VERSION 5.8 ;
BUSBITCHARS "[]" ;
DIVIDERCHAR "/" ;
UNITS
    DATABASE MICRONS 1000 ;
END UNITS

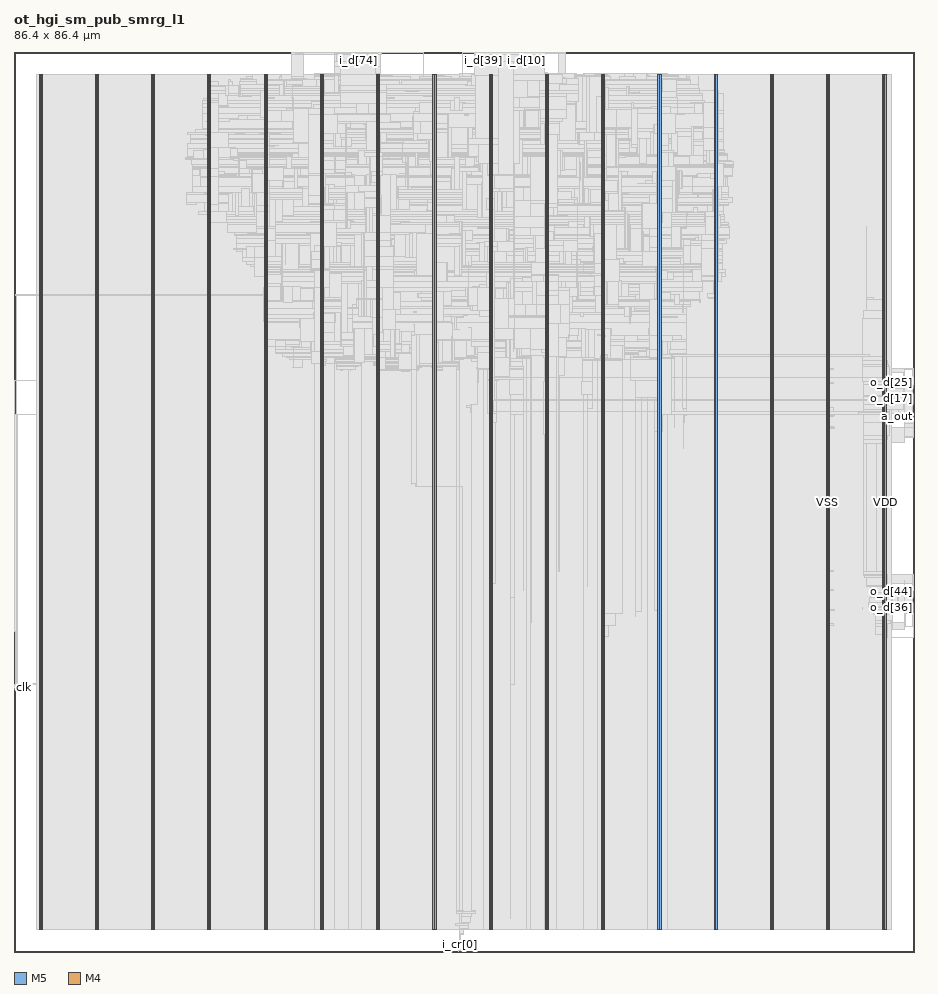
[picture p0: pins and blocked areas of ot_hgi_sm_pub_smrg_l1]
MACRO ot_hgi_sm_pub_smrg_l1
  FOREIGN ot_hgi_sm_pub_smrg_l1 0 0 ;
  CLASS BLOCK ;
  SIZE 86.4 BY 86.4 ;
  PIN a_in[0]
    DIRECTION INPUT ;
    USE SIGNAL ;
    PORT
      LAYER M5 ;
        RECT  48.048 86.316 48.072 86.4 ;
    END
  END a_in[0]
  PIN a_in[1]
    DIRECTION INPUT ;
    USE SIGNAL ;
    PORT
      LAYER M5 ;
        RECT  48.144 86.316 48.168 86.4 ;
    END
  END a_in[1]
  PIN a_out
    DIRECTION OUTPUT ;
    USE SIGNAL ;
    PORT
      LAYER M4 ;
        RECT  86.316 51.408 86.4 51.432 ;
    END
  END a_out
  PIN clk
    DIRECTION INPUT ;
    USE SIGNAL ;
    PORT
      LAYER M4 ;
        RECT  0 25.392 0.084 25.416 ;
    END
  END clk
  PIN i_cr[0]
    DIRECTION OUTPUT ;
    USE SIGNAL ;
    PORT
      LAYER M5 ;
        RECT  42.768 0 42.792 0.084 ;
    END
  END i_cr[0]
  PIN i_cr[1]
    DIRECTION OUTPUT ;
    USE SIGNAL ;
    PORT
      LAYER M5 ;
        RECT  42.864 0 42.888 0.084 ;
    END
  END i_cr[1]
  PIN i_d[0]
    DIRECTION INPUT ;
    USE SIGNAL ;
    PORT
      LAYER M5 ;
        RECT  48.24 86.316 48.264 86.4 ;
    END
  END i_d[0]
  PIN i_d[100]
    DIRECTION INPUT ;
    USE SIGNAL ;
    PORT
      LAYER M5 ;
        RECT  31.344 86.316 31.368 86.4 ;
    END
  END i_d[100]
  PIN i_d[101]
    DIRECTION INPUT ;
    USE SIGNAL ;
    PORT
      LAYER M5 ;
        RECT  31.44 86.316 31.464 86.4 ;
    END
  END i_d[101]
  PIN i_d[102]
    DIRECTION INPUT ;
    USE SIGNAL ;
    PORT
      LAYER M5 ;
        RECT  31.536 86.316 31.56 86.4 ;
    END
  END i_d[102]
  PIN i_d[103]
    DIRECTION INPUT ;
    USE SIGNAL ;
    PORT
      LAYER M5 ;
        RECT  31.632 86.316 31.656 86.4 ;
    END
  END i_d[103]
  PIN i_d[10]
    DIRECTION INPUT ;
    USE SIGNAL ;
    PORT
      LAYER M5 ;
        RECT  49.2 86.316 49.224 86.4 ;
    END
  END i_d[10]
  PIN i_d[11]
    DIRECTION INPUT ;
    USE SIGNAL ;
    PORT
      LAYER M5 ;
        RECT  49.296 86.316 49.32 86.4 ;
    END
  END i_d[11]
  PIN i_d[12]
    DIRECTION INPUT ;
    USE SIGNAL ;
    PORT
      LAYER M5 ;
        RECT  49.392 86.316 49.416 86.4 ;
    END
  END i_d[12]
  PIN i_d[13]
    DIRECTION INPUT ;
    USE SIGNAL ;
    PORT
      LAYER M5 ;
        RECT  49.488 86.316 49.512 86.4 ;
    END
  END i_d[13]
  PIN i_d[14]
    DIRECTION INPUT ;
    USE SIGNAL ;
    PORT
      LAYER M5 ;
        RECT  49.584 86.316 49.608 86.4 ;
    END
  END i_d[14]
  PIN i_d[15]
    DIRECTION INPUT ;
    USE SIGNAL ;
    PORT
      LAYER M5 ;
        RECT  49.68 86.316 49.704 86.4 ;
    END
  END i_d[15]
  PIN i_d[16]
    DIRECTION INPUT ;
    USE SIGNAL ;
    PORT
      LAYER M5 ;
        RECT  49.776 86.316 49.8 86.4 ;
    END
  END i_d[16]
  PIN i_d[17]
    DIRECTION INPUT ;
    USE SIGNAL ;
    PORT
      LAYER M5 ;
        RECT  49.872 86.316 49.896 86.4 ;
    END
  END i_d[17]
  PIN i_d[18]
    DIRECTION INPUT ;
    USE SIGNAL ;
    PORT
      LAYER M5 ;
        RECT  49.968 86.316 49.992 86.4 ;
    END
  END i_d[18]
  PIN i_d[19]
    DIRECTION INPUT ;
    USE SIGNAL ;
    PORT
      LAYER M5 ;
        RECT  50.064 86.316 50.088 86.4 ;
    END
  END i_d[19]
  PIN i_d[1]
    DIRECTION INPUT ;
    USE SIGNAL ;
    PORT
      LAYER M5 ;
        RECT  48.336 86.316 48.36 86.4 ;
    END
  END i_d[1]
  PIN i_d[20]
    DIRECTION INPUT ;
    USE SIGNAL ;
    PORT
      LAYER M5 ;
        RECT  50.16 86.316 50.184 86.4 ;
    END
  END i_d[20]
  PIN i_d[21]
    DIRECTION INPUT ;
    USE SIGNAL ;
    PORT
      LAYER M5 ;
        RECT  50.256 86.316 50.28 86.4 ;
    END
  END i_d[21]
  PIN i_d[22]
    DIRECTION INPUT ;
    USE SIGNAL ;
    PORT
      LAYER M5 ;
        RECT  50.352 86.316 50.376 86.4 ;
    END
  END i_d[22]
  PIN i_d[23]
    DIRECTION INPUT ;
    USE SIGNAL ;
    PORT
      LAYER M5 ;
        RECT  50.448 86.316 50.472 86.4 ;
    END
  END i_d[23]
  PIN i_d[24]
    DIRECTION INPUT ;
    USE SIGNAL ;
    PORT
      LAYER M5 ;
        RECT  50.544 86.316 50.568 86.4 ;
    END
  END i_d[24]
  PIN i_d[25]
    DIRECTION INPUT ;
    USE SIGNAL ;
    PORT
      LAYER M5 ;
        RECT  50.64 86.316 50.664 86.4 ;
    END
  END i_d[25]
  PIN i_d[26]
    DIRECTION INPUT ;
    USE SIGNAL ;
    PORT
      LAYER M5 ;
        RECT  50.736 86.316 50.76 86.4 ;
    END
  END i_d[26]
  PIN i_d[27]
    DIRECTION INPUT ;
    USE SIGNAL ;
    PORT
      LAYER M5 ;
        RECT  50.832 86.316 50.856 86.4 ;
    END
  END i_d[27]
  PIN i_d[28]
    DIRECTION INPUT ;
    USE SIGNAL ;
    PORT
      LAYER M5 ;
        RECT  50.928 86.316 50.952 86.4 ;
    END
  END i_d[28]
  PIN i_d[29]
    DIRECTION INPUT ;
    USE SIGNAL ;
    PORT
      LAYER M5 ;
        RECT  51.024 86.316 51.048 86.4 ;
    END
  END i_d[29]
  PIN i_d[2]
    DIRECTION INPUT ;
    USE SIGNAL ;
    PORT
      LAYER M5 ;
        RECT  48.432 86.316 48.456 86.4 ;
    END
  END i_d[2]
  PIN i_d[30]
    DIRECTION INPUT ;
    USE SIGNAL ;
    PORT
      LAYER M5 ;
        RECT  44.208 86.316 44.232 86.4 ;
    END
  END i_d[30]
  PIN i_d[31]
    DIRECTION INPUT ;
    USE SIGNAL ;
    PORT
      LAYER M5 ;
        RECT  44.304 86.316 44.328 86.4 ;
    END
  END i_d[31]
  PIN i_d[32]
    DIRECTION INPUT ;
    USE SIGNAL ;
    PORT
      LAYER M5 ;
        RECT  44.4 86.316 44.424 86.4 ;
    END
  END i_d[32]
  PIN i_d[33]
    DIRECTION INPUT ;
    USE SIGNAL ;
    PORT
      LAYER M5 ;
        RECT  44.496 86.316 44.52 86.4 ;
    END
  END i_d[33]
  PIN i_d[34]
    DIRECTION INPUT ;
    USE SIGNAL ;
    PORT
      LAYER M5 ;
        RECT  44.592 86.316 44.616 86.4 ;
    END
  END i_d[34]
  PIN i_d[35]
    DIRECTION INPUT ;
    USE SIGNAL ;
    PORT
      LAYER M5 ;
        RECT  44.688 86.316 44.712 86.4 ;
    END
  END i_d[35]
  PIN i_d[36]
    DIRECTION INPUT ;
    USE SIGNAL ;
    PORT
      LAYER M5 ;
        RECT  44.784 86.316 44.808 86.4 ;
    END
  END i_d[36]
  PIN i_d[37]
    DIRECTION INPUT ;
    USE SIGNAL ;
    PORT
      LAYER M5 ;
        RECT  44.88 86.316 44.904 86.4 ;
    END
  END i_d[37]
  PIN i_d[38]
    DIRECTION INPUT ;
    USE SIGNAL ;
    PORT
      LAYER M5 ;
        RECT  44.976 86.316 45 86.4 ;
    END
  END i_d[38]
  PIN i_d[39]
    DIRECTION INPUT ;
    USE SIGNAL ;
    PORT
      LAYER M5 ;
        RECT  45.072 86.316 45.096 86.4 ;
    END
  END i_d[39]
  PIN i_d[3]
    DIRECTION INPUT ;
    USE SIGNAL ;
    PORT
      LAYER M5 ;
        RECT  48.528 86.316 48.552 86.4 ;
    END
  END i_d[3]
  PIN i_d[40]
    DIRECTION INPUT ;
    USE SIGNAL ;
    PORT
      LAYER M5 ;
        RECT  45.168 86.316 45.192 86.4 ;
    END
  END i_d[40]
  PIN i_d[41]
    DIRECTION INPUT ;
    USE SIGNAL ;
    PORT
      LAYER M5 ;
        RECT  45.264 86.316 45.288 86.4 ;
    END
  END i_d[41]
  PIN i_d[42]
    DIRECTION INPUT ;
    USE SIGNAL ;
    PORT
      LAYER M5 ;
        RECT  45.36 86.316 45.384 86.4 ;
    END
  END i_d[42]
  PIN i_d[43]
    DIRECTION INPUT ;
    USE SIGNAL ;
    PORT
      LAYER M5 ;
        RECT  45.456 86.316 45.48 86.4 ;
    END
  END i_d[43]
  PIN i_d[44]
    DIRECTION INPUT ;
    USE SIGNAL ;
    PORT
      LAYER M5 ;
        RECT  45.552 86.316 45.576 86.4 ;
    END
  END i_d[44]
  PIN i_d[45]
    DIRECTION INPUT ;
    USE SIGNAL ;
    PORT
      LAYER M5 ;
        RECT  45.648 86.316 45.672 86.4 ;
    END
  END i_d[45]
  PIN i_d[46]
    DIRECTION INPUT ;
    USE SIGNAL ;
    PORT
      LAYER M5 ;
        RECT  45.744 86.316 45.768 86.4 ;
    END
  END i_d[46]
  PIN i_d[47]
    DIRECTION INPUT ;
    USE SIGNAL ;
    PORT
      LAYER M5 ;
        RECT  45.84 86.316 45.864 86.4 ;
    END
  END i_d[47]
  PIN i_d[48]
    DIRECTION INPUT ;
    USE SIGNAL ;
    PORT
      LAYER M5 ;
        RECT  45.936 86.316 45.96 86.4 ;
    END
  END i_d[48]
  PIN i_d[49]
    DIRECTION INPUT ;
    USE SIGNAL ;
    PORT
      LAYER M5 ;
        RECT  46.032 86.316 46.056 86.4 ;
    END
  END i_d[49]
  PIN i_d[4]
    DIRECTION INPUT ;
    USE SIGNAL ;
    PORT
      LAYER M5 ;
        RECT  48.624 86.316 48.648 86.4 ;
    END
  END i_d[4]
  PIN i_d[50]
    DIRECTION INPUT ;
    USE SIGNAL ;
    PORT
      LAYER M5 ;
        RECT  46.128 86.316 46.152 86.4 ;
    END
  END i_d[50]
  PIN i_d[51]
    DIRECTION INPUT ;
    USE SIGNAL ;
    PORT
      LAYER M5 ;
        RECT  46.224 86.316 46.248 86.4 ;
    END
  END i_d[51]
  PIN i_d[52]
    DIRECTION INPUT ;
    USE SIGNAL ;
    PORT
      LAYER M5 ;
        RECT  46.32 86.316 46.344 86.4 ;
    END
  END i_d[52]
  PIN i_d[53]
    DIRECTION INPUT ;
    USE SIGNAL ;
    PORT
      LAYER M5 ;
        RECT  46.416 86.316 46.44 86.4 ;
    END
  END i_d[53]
  PIN i_d[54]
    DIRECTION INPUT ;
    USE SIGNAL ;
    PORT
      LAYER M5 ;
        RECT  46.512 86.316 46.536 86.4 ;
    END
  END i_d[54]
  PIN i_d[55]
    DIRECTION INPUT ;
    USE SIGNAL ;
    PORT
      LAYER M5 ;
        RECT  46.608 86.316 46.632 86.4 ;
    END
  END i_d[55]
  PIN i_d[56]
    DIRECTION INPUT ;
    USE SIGNAL ;
    PORT
      LAYER M5 ;
        RECT  46.704 86.316 46.728 86.4 ;
    END
  END i_d[56]
  PIN i_d[57]
    DIRECTION INPUT ;
    USE SIGNAL ;
    PORT
      LAYER M5 ;
        RECT  46.8 86.316 46.824 86.4 ;
    END
  END i_d[57]
  PIN i_d[58]
    DIRECTION INPUT ;
    USE SIGNAL ;
    PORT
      LAYER M5 ;
        RECT  46.896 86.316 46.92 86.4 ;
    END
  END i_d[58]
  PIN i_d[59]
    DIRECTION INPUT ;
    USE SIGNAL ;
    PORT
      LAYER M5 ;
        RECT  46.992 86.316 47.016 86.4 ;
    END
  END i_d[59]
  PIN i_d[5]
    DIRECTION INPUT ;
    USE SIGNAL ;
    PORT
      LAYER M5 ;
        RECT  48.72 86.316 48.744 86.4 ;
    END
  END i_d[5]
  PIN i_d[60]
    DIRECTION INPUT ;
    USE SIGNAL ;
    PORT
      LAYER M5 ;
        RECT  47.088 86.316 47.112 86.4 ;
    END
  END i_d[60]
  PIN i_d[61]
    DIRECTION INPUT ;
    USE SIGNAL ;
    PORT
      LAYER M5 ;
        RECT  47.184 86.316 47.208 86.4 ;
    END
  END i_d[61]
  PIN i_d[62]
    DIRECTION INPUT ;
    USE SIGNAL ;
    PORT
      LAYER M5 ;
        RECT  31.92 86.316 31.944 86.4 ;
    END
  END i_d[62]
  PIN i_d[63]
    DIRECTION INPUT ;
    USE SIGNAL ;
    PORT
      LAYER M5 ;
        RECT  32.016 86.316 32.04 86.4 ;
    END
  END i_d[63]
  PIN i_d[64]
    DIRECTION INPUT ;
    USE SIGNAL ;
    PORT
      LAYER M5 ;
        RECT  32.112 86.316 32.136 86.4 ;
    END
  END i_d[64]
  PIN i_d[65]
    DIRECTION INPUT ;
    USE SIGNAL ;
    PORT
      LAYER M5 ;
        RECT  32.208 86.316 32.232 86.4 ;
    END
  END i_d[65]
  PIN i_d[66]
    DIRECTION INPUT ;
    USE SIGNAL ;
    PORT
      LAYER M5 ;
        RECT  32.304 86.316 32.328 86.4 ;
    END
  END i_d[66]
  PIN i_d[67]
    DIRECTION INPUT ;
    USE SIGNAL ;
    PORT
      LAYER M5 ;
        RECT  32.4 86.316 32.424 86.4 ;
    END
  END i_d[67]
  PIN i_d[68]
    DIRECTION INPUT ;
    USE SIGNAL ;
    PORT
      LAYER M5 ;
        RECT  32.496 86.316 32.52 86.4 ;
    END
  END i_d[68]
  PIN i_d[69]
    DIRECTION INPUT ;
    USE SIGNAL ;
    PORT
      LAYER M5 ;
        RECT  32.592 86.316 32.616 86.4 ;
    END
  END i_d[69]
  PIN i_d[6]
    DIRECTION INPUT ;
    USE SIGNAL ;
    PORT
      LAYER M5 ;
        RECT  48.816 86.316 48.84 86.4 ;
    END
  END i_d[6]
  PIN i_d[70]
    DIRECTION INPUT ;
    USE SIGNAL ;
    PORT
      LAYER M5 ;
        RECT  32.688 86.316 32.712 86.4 ;
    END
  END i_d[70]
  PIN i_d[71]
    DIRECTION INPUT ;
    USE SIGNAL ;
    PORT
      LAYER M5 ;
        RECT  32.784 86.316 32.808 86.4 ;
    END
  END i_d[71]
  PIN i_d[72]
    DIRECTION INPUT ;
    USE SIGNAL ;
    PORT
      LAYER M5 ;
        RECT  32.88 86.316 32.904 86.4 ;
    END
  END i_d[72]
  PIN i_d[73]
    DIRECTION INPUT ;
    USE SIGNAL ;
    PORT
      LAYER M5 ;
        RECT  32.976 86.316 33 86.4 ;
    END
  END i_d[73]
  PIN i_d[74]
    DIRECTION INPUT ;
    USE SIGNAL ;
    PORT
      LAYER M5 ;
        RECT  33.072 86.316 33.096 86.4 ;
    END
  END i_d[74]
  PIN i_d[75]
    DIRECTION INPUT ;
    USE SIGNAL ;
    PORT
      LAYER M5 ;
        RECT  33.168 86.316 33.192 86.4 ;
    END
  END i_d[75]
  PIN i_d[76]
    DIRECTION INPUT ;
    USE SIGNAL ;
    PORT
      LAYER M5 ;
        RECT  33.264 86.316 33.288 86.4 ;
    END
  END i_d[76]
  PIN i_d[77]
    DIRECTION INPUT ;
    USE SIGNAL ;
    PORT
      LAYER M5 ;
        RECT  33.36 86.316 33.384 86.4 ;
    END
  END i_d[77]
  PIN i_d[78]
    DIRECTION INPUT ;
    USE SIGNAL ;
    PORT
      LAYER M5 ;
        RECT  33.456 86.316 33.48 86.4 ;
    END
  END i_d[78]
  PIN i_d[79]
    DIRECTION INPUT ;
    USE SIGNAL ;
    PORT
      LAYER M5 ;
        RECT  33.552 86.316 33.576 86.4 ;
    END
  END i_d[79]
  PIN i_d[7]
    DIRECTION INPUT ;
    USE SIGNAL ;
    PORT
      LAYER M5 ;
        RECT  48.912 86.316 48.936 86.4 ;
    END
  END i_d[7]
  PIN i_d[80]
    DIRECTION INPUT ;
    USE SIGNAL ;
    PORT
      LAYER M5 ;
        RECT  33.648 86.316 33.672 86.4 ;
    END
  END i_d[80]
  PIN i_d[81]
    DIRECTION INPUT ;
    USE SIGNAL ;
    PORT
      LAYER M5 ;
        RECT  33.744 86.316 33.768 86.4 ;
    END
  END i_d[81]
  PIN i_d[82]
    DIRECTION INPUT ;
    USE SIGNAL ;
    PORT
      LAYER M5 ;
        RECT  33.84 86.316 33.864 86.4 ;
    END
  END i_d[82]
  PIN i_d[83]
    DIRECTION INPUT ;
    USE SIGNAL ;
    PORT
      LAYER M5 ;
        RECT  33.936 86.316 33.96 86.4 ;
    END
  END i_d[83]
  PIN i_d[84]
    DIRECTION INPUT ;
    USE SIGNAL ;
    PORT
      LAYER M5 ;
        RECT  34.032 86.316 34.056 86.4 ;
    END
  END i_d[84]
  PIN i_d[85]
    DIRECTION INPUT ;
    USE SIGNAL ;
    PORT
      LAYER M5 ;
        RECT  34.128 86.316 34.152 86.4 ;
    END
  END i_d[85]
  PIN i_d[86]
    DIRECTION INPUT ;
    USE SIGNAL ;
    PORT
      LAYER M5 ;
        RECT  34.224 86.316 34.248 86.4 ;
    END
  END i_d[86]
  PIN i_d[87]
    DIRECTION INPUT ;
    USE SIGNAL ;
    PORT
      LAYER M5 ;
        RECT  34.32 86.316 34.344 86.4 ;
    END
  END i_d[87]
  PIN i_d[88]
    DIRECTION INPUT ;
    USE SIGNAL ;
    PORT
      LAYER M5 ;
        RECT  34.416 86.316 34.44 86.4 ;
    END
  END i_d[88]
  PIN i_d[89]
    DIRECTION INPUT ;
    USE SIGNAL ;
    PORT
      LAYER M5 ;
        RECT  34.512 86.316 34.536 86.4 ;
    END
  END i_d[89]
  PIN i_d[8]
    DIRECTION INPUT ;
    USE SIGNAL ;
    PORT
      LAYER M5 ;
        RECT  49.008 86.316 49.032 86.4 ;
    END
  END i_d[8]
  PIN i_d[90]
    DIRECTION INPUT ;
    USE SIGNAL ;
    PORT
      LAYER M5 ;
        RECT  34.608 86.316 34.632 86.4 ;
    END
  END i_d[90]
  PIN i_d[91]
    DIRECTION INPUT ;
    USE SIGNAL ;
    PORT
      LAYER M5 ;
        RECT  34.704 86.316 34.728 86.4 ;
    END
  END i_d[91]
  PIN i_d[92]
    DIRECTION INPUT ;
    USE SIGNAL ;
    PORT
      LAYER M5 ;
        RECT  34.8 86.316 34.824 86.4 ;
    END
  END i_d[92]
  PIN i_d[93]
    DIRECTION INPUT ;
    USE SIGNAL ;
    PORT
      LAYER M5 ;
        RECT  34.896 86.316 34.92 86.4 ;
    END
  END i_d[93]
  PIN i_d[94]
    DIRECTION INPUT ;
    USE SIGNAL ;
    PORT
      LAYER M5 ;
        RECT  30.768 86.316 30.792 86.4 ;
    END
  END i_d[94]
  PIN i_d[95]
    DIRECTION INPUT ;
    USE SIGNAL ;
    PORT
      LAYER M5 ;
        RECT  30.864 86.316 30.888 86.4 ;
    END
  END i_d[95]
  PIN i_d[96]
    DIRECTION INPUT ;
    USE SIGNAL ;
    PORT
      LAYER M5 ;
        RECT  30.96 86.316 30.984 86.4 ;
    END
  END i_d[96]
  PIN i_d[97]
    DIRECTION INPUT ;
    USE SIGNAL ;
    PORT
      LAYER M5 ;
        RECT  31.056 86.316 31.08 86.4 ;
    END
  END i_d[97]
  PIN i_d[98]
    DIRECTION INPUT ;
    USE SIGNAL ;
    PORT
      LAYER M5 ;
        RECT  31.152 86.316 31.176 86.4 ;
    END
  END i_d[98]
  PIN i_d[99]
    DIRECTION INPUT ;
    USE SIGNAL ;
    PORT
      LAYER M5 ;
        RECT  31.248 86.316 31.272 86.4 ;
    END
  END i_d[99]
  PIN i_d[9]
    DIRECTION INPUT ;
    USE SIGNAL ;
    PORT
      LAYER M5 ;
        RECT  49.104 86.316 49.128 86.4 ;
    END
  END i_d[9]
  PIN i_v[0]
    DIRECTION INPUT ;
    USE SIGNAL ;
    PORT
      LAYER M5 ;
        RECT  31.728 86.316 31.752 86.4 ;
    END
  END i_v[0]
  PIN i_v[1]
    DIRECTION INPUT ;
    USE SIGNAL ;
    PORT
      LAYER M5 ;
        RECT  31.824 86.316 31.848 86.4 ;
    END
  END i_v[1]
  PIN o_cr
    DIRECTION INPUT ;
    USE SIGNAL ;
    PORT
      LAYER M4 ;
        RECT  0 25.488 0.084 25.512 ;
    END
  END o_cr
  PIN o_d[0]
    DIRECTION OUTPUT ;
    USE SIGNAL ;
    PORT
      LAYER M4 ;
        RECT  86.316 51.504 86.4 51.528 ;
    END
  END o_d[0]
  PIN o_d[10]
    DIRECTION OUTPUT ;
    USE SIGNAL ;
    PORT
      LAYER M4 ;
        RECT  86.316 52.464 86.4 52.488 ;
    END
  END o_d[10]
  PIN o_d[11]
    DIRECTION OUTPUT ;
    USE SIGNAL ;
    PORT
      LAYER M4 ;
        RECT  86.316 52.56 86.4 52.584 ;
    END
  END o_d[11]
  PIN o_d[12]
    DIRECTION OUTPUT ;
    USE SIGNAL ;
    PORT
      LAYER M4 ;
        RECT  86.316 52.656 86.4 52.68 ;
    END
  END o_d[12]
  PIN o_d[13]
    DIRECTION OUTPUT ;
    USE SIGNAL ;
    PORT
      LAYER M4 ;
        RECT  86.316 52.752 86.4 52.776 ;
    END
  END o_d[13]
  PIN o_d[14]
    DIRECTION OUTPUT ;
    USE SIGNAL ;
    PORT
      LAYER M4 ;
        RECT  86.316 52.848 86.4 52.872 ;
    END
  END o_d[14]
  PIN o_d[15]
    DIRECTION OUTPUT ;
    USE SIGNAL ;
    PORT
      LAYER M4 ;
        RECT  86.316 52.944 86.4 52.968 ;
    END
  END o_d[15]
  PIN o_d[16]
    DIRECTION OUTPUT ;
    USE SIGNAL ;
    PORT
      LAYER M4 ;
        RECT  86.316 53.04 86.4 53.064 ;
    END
  END o_d[16]
  PIN o_d[17]
    DIRECTION OUTPUT ;
    USE SIGNAL ;
    PORT
      LAYER M4 ;
        RECT  86.316 53.136 86.4 53.16 ;
    END
  END o_d[17]
  PIN o_d[18]
    DIRECTION OUTPUT ;
    USE SIGNAL ;
    PORT
      LAYER M4 ;
        RECT  86.316 53.232 86.4 53.256 ;
    END
  END o_d[18]
  PIN o_d[19]
    DIRECTION OUTPUT ;
    USE SIGNAL ;
    PORT
      LAYER M4 ;
        RECT  86.316 53.328 86.4 53.352 ;
    END
  END o_d[19]
  PIN o_d[1]
    DIRECTION OUTPUT ;
    USE SIGNAL ;
    PORT
      LAYER M4 ;
        RECT  86.316 51.6 86.4 51.624 ;
    END
  END o_d[1]
  PIN o_d[20]
    DIRECTION OUTPUT ;
    USE SIGNAL ;
    PORT
      LAYER M4 ;
        RECT  86.316 53.424 86.4 53.448 ;
    END
  END o_d[20]
  PIN o_d[21]
    DIRECTION OUTPUT ;
    USE SIGNAL ;
    PORT
      LAYER M4 ;
        RECT  86.316 53.52 86.4 53.544 ;
    END
  END o_d[21]
  PIN o_d[22]
    DIRECTION OUTPUT ;
    USE SIGNAL ;
    PORT
      LAYER M4 ;
        RECT  86.316 53.616 86.4 53.64 ;
    END
  END o_d[22]
  PIN o_d[23]
    DIRECTION OUTPUT ;
    USE SIGNAL ;
    PORT
      LAYER M4 ;
        RECT  86.316 53.712 86.4 53.736 ;
    END
  END o_d[23]
  PIN o_d[24]
    DIRECTION OUTPUT ;
    USE SIGNAL ;
    PORT
      LAYER M4 ;
        RECT  86.316 53.808 86.4 53.832 ;
    END
  END o_d[24]
  PIN o_d[25]
    DIRECTION OUTPUT ;
    USE SIGNAL ;
    PORT
      LAYER M4 ;
        RECT  86.316 53.904 86.4 53.928 ;
    END
  END o_d[25]
  PIN o_d[26]
    DIRECTION OUTPUT ;
    USE SIGNAL ;
    PORT
      LAYER M4 ;
        RECT  86.316 54 86.4 54.024 ;
    END
  END o_d[26]
  PIN o_d[27]
    DIRECTION OUTPUT ;
    USE SIGNAL ;
    PORT
      LAYER M4 ;
        RECT  86.316 54.096 86.4 54.12 ;
    END
  END o_d[27]
  PIN o_d[28]
    DIRECTION OUTPUT ;
    USE SIGNAL ;
    PORT
      LAYER M4 ;
        RECT  86.316 54.192 86.4 54.216 ;
    END
  END o_d[28]
  PIN o_d[29]
    DIRECTION OUTPUT ;
    USE SIGNAL ;
    PORT
      LAYER M4 ;
        RECT  86.316 54.288 86.4 54.312 ;
    END
  END o_d[29]
  PIN o_d[2]
    DIRECTION OUTPUT ;
    USE SIGNAL ;
    PORT
      LAYER M4 ;
        RECT  86.316 51.696 86.4 51.72 ;
    END
  END o_d[2]
  PIN o_d[30]
    DIRECTION OUTPUT ;
    USE SIGNAL ;
    PORT
      LAYER M4 ;
        RECT  86.316 54.384 86.4 54.408 ;
    END
  END o_d[30]
  PIN o_d[31]
    DIRECTION OUTPUT ;
    USE SIGNAL ;
    PORT
      LAYER M4 ;
        RECT  86.316 32.592 86.4 32.616 ;
    END
  END o_d[31]
  PIN o_d[32]
    DIRECTION OUTPUT ;
    USE SIGNAL ;
    PORT
      LAYER M4 ;
        RECT  86.316 32.688 86.4 32.712 ;
    END
  END o_d[32]
  PIN o_d[33]
    DIRECTION OUTPUT ;
    USE SIGNAL ;
    PORT
      LAYER M4 ;
        RECT  86.316 32.784 86.4 32.808 ;
    END
  END o_d[33]
  PIN o_d[34]
    DIRECTION OUTPUT ;
    USE SIGNAL ;
    PORT
      LAYER M4 ;
        RECT  86.316 32.88 86.4 32.904 ;
    END
  END o_d[34]
  PIN o_d[35]
    DIRECTION OUTPUT ;
    USE SIGNAL ;
    PORT
      LAYER M4 ;
        RECT  86.316 32.976 86.4 33 ;
    END
  END o_d[35]
  PIN o_d[36]
    DIRECTION OUTPUT ;
    USE SIGNAL ;
    PORT
      LAYER M4 ;
        RECT  86.316 33.072 86.4 33.096 ;
    END
  END o_d[36]
  PIN o_d[37]
    DIRECTION OUTPUT ;
    USE SIGNAL ;
    PORT
      LAYER M4 ;
        RECT  86.316 33.168 86.4 33.192 ;
    END
  END o_d[37]
  PIN o_d[38]
    DIRECTION OUTPUT ;
    USE SIGNAL ;
    PORT
      LAYER M4 ;
        RECT  86.316 33.264 86.4 33.288 ;
    END
  END o_d[38]
  PIN o_d[39]
    DIRECTION OUTPUT ;
    USE SIGNAL ;
    PORT
      LAYER M4 ;
        RECT  86.316 33.36 86.4 33.384 ;
    END
  END o_d[39]
  PIN o_d[3]
    DIRECTION OUTPUT ;
    USE SIGNAL ;
    PORT
      LAYER M4 ;
        RECT  86.316 51.792 86.4 51.816 ;
    END
  END o_d[3]
  PIN o_d[40]
    DIRECTION OUTPUT ;
    USE SIGNAL ;
    PORT
      LAYER M4 ;
        RECT  86.316 33.456 86.4 33.48 ;
    END
  END o_d[40]
  PIN o_d[41]
    DIRECTION OUTPUT ;
    USE SIGNAL ;
    PORT
      LAYER M4 ;
        RECT  86.316 33.552 86.4 33.576 ;
    END
  END o_d[41]
  PIN o_d[42]
    DIRECTION OUTPUT ;
    USE SIGNAL ;
    PORT
      LAYER M4 ;
        RECT  86.316 33.648 86.4 33.672 ;
    END
  END o_d[42]
  PIN o_d[43]
    DIRECTION OUTPUT ;
    USE SIGNAL ;
    PORT
      LAYER M4 ;
        RECT  86.316 33.744 86.4 33.768 ;
    END
  END o_d[43]
  PIN o_d[44]
    DIRECTION OUTPUT ;
    USE SIGNAL ;
    PORT
      LAYER M4 ;
        RECT  86.316 33.84 86.4 33.864 ;
    END
  END o_d[44]
  PIN o_d[45]
    DIRECTION OUTPUT ;
    USE SIGNAL ;
    PORT
      LAYER M4 ;
        RECT  86.316 33.936 86.4 33.96 ;
    END
  END o_d[45]
  PIN o_d[46]
    DIRECTION OUTPUT ;
    USE SIGNAL ;
    PORT
      LAYER M4 ;
        RECT  86.316 34.032 86.4 34.056 ;
    END
  END o_d[46]
  PIN o_d[47]
    DIRECTION OUTPUT ;
    USE SIGNAL ;
    PORT
      LAYER M4 ;
        RECT  86.316 34.128 86.4 34.152 ;
    END
  END o_d[47]
  PIN o_d[48]
    DIRECTION OUTPUT ;
    USE SIGNAL ;
    PORT
      LAYER M4 ;
        RECT  86.316 34.224 86.4 34.248 ;
    END
  END o_d[48]
  PIN o_d[49]
    DIRECTION OUTPUT ;
    USE SIGNAL ;
    PORT
      LAYER M4 ;
        RECT  86.316 34.32 86.4 34.344 ;
    END
  END o_d[49]
  PIN o_d[4]
    DIRECTION OUTPUT ;
    USE SIGNAL ;
    PORT
      LAYER M4 ;
        RECT  86.316 51.888 86.4 51.912 ;
    END
  END o_d[4]
  PIN o_d[50]
    DIRECTION OUTPUT ;
    USE SIGNAL ;
    PORT
      LAYER M4 ;
        RECT  86.316 34.416 86.4 34.44 ;
    END
  END o_d[50]
  PIN o_d[51]
    DIRECTION OUTPUT ;
    USE SIGNAL ;
    PORT
      LAYER M4 ;
        RECT  86.316 34.512 86.4 34.536 ;
    END
  END o_d[51]
  PIN o_d[5]
    DIRECTION OUTPUT ;
    USE SIGNAL ;
    PORT
      LAYER M4 ;
        RECT  86.316 51.984 86.4 52.008 ;
    END
  END o_d[5]
  PIN o_d[6]
    DIRECTION OUTPUT ;
    USE SIGNAL ;
    PORT
      LAYER M4 ;
        RECT  86.316 52.08 86.4 52.104 ;
    END
  END o_d[6]
  PIN o_d[7]
    DIRECTION OUTPUT ;
    USE SIGNAL ;
    PORT
      LAYER M4 ;
        RECT  86.316 52.176 86.4 52.2 ;
    END
  END o_d[7]
  PIN o_d[8]
    DIRECTION OUTPUT ;
    USE SIGNAL ;
    PORT
      LAYER M4 ;
        RECT  86.316 52.272 86.4 52.296 ;
    END
  END o_d[8]
  PIN o_d[9]
    DIRECTION OUTPUT ;
    USE SIGNAL ;
    PORT
      LAYER M4 ;
        RECT  86.316 52.368 86.4 52.392 ;
    END
  END o_d[9]
  PIN o_v
    DIRECTION OUTPUT ;
    USE SIGNAL ;
    PORT
      LAYER M4 ;
        RECT  86.316 34.608 86.4 34.632 ;
    END
  END o_v
  PIN rn
    DIRECTION INPUT ;
    USE SIGNAL ;
    PORT
      LAYER M4 ;
        RECT  0 25.584 0.084 25.608 ;
    END
  END rn
  PIN xb
    DIRECTION INPUT ;
    USE SIGNAL ;
    PORT
      LAYER M4 ;
        RECT  0 25.68 0.084 25.704 ;
    END
  END xb
  PIN VDD
    DIRECTION INOUT ;
    USE POWER ;
    PORT
      LAYER M5 ;
        RECT  83.592 2.151 83.712 84.249 ;
        RECT  78.192 2.151 78.312 84.249 ;
        RECT  72.792 2.151 72.912 84.249 ;
        RECT  67.392 2.151 67.512 84.249 ;
        RECT  61.992 2.151 62.112 84.249 ;
        RECT  56.592 2.151 56.712 84.249 ;
        RECT  51.192 2.151 51.312 84.249 ;
        RECT  45.792 2.151 45.912 84.249 ;
        RECT  40.392 2.151 40.512 84.249 ;
        RECT  34.992 2.151 35.112 84.249 ;
        RECT  29.592 2.151 29.712 84.249 ;
        RECT  24.192 2.151 24.312 84.249 ;
        RECT  18.792 2.151 18.912 84.249 ;
        RECT  13.392 2.151 13.512 84.249 ;
        RECT  7.992 2.151 8.112 84.249 ;
        RECT  2.592 2.151 2.712 84.249 ;
    END
  END VDD
  PIN VSS
    DIRECTION INOUT ;
    USE GROUND ;
    PORT
      LAYER M5 ;
        RECT  83.4 2.137 83.52 84.263 ;
        RECT  78 2.137 78.12 84.263 ;
        RECT  72.6 2.137 72.72 84.263 ;
        RECT  67.2 2.137 67.32 84.263 ;
        RECT  61.8 2.137 61.92 84.263 ;
        RECT  56.4 2.137 56.52 84.263 ;
        RECT  51 2.137 51.12 84.263 ;
        RECT  45.6 2.137 45.72 84.263 ;
        RECT  40.2 2.137 40.32 84.263 ;
        RECT  34.8 2.137 34.92 84.263 ;
        RECT  29.4 2.137 29.52 84.263 ;
        RECT  24 2.137 24.12 84.263 ;
        RECT  18.6 2.137 18.72 84.263 ;
        RECT  13.2 2.137 13.32 84.263 ;
        RECT  7.8 2.137 7.92 84.263 ;
        RECT  2.4 2.137 2.52 84.263 ;
    END
  END VSS
  # OT_OBS_CLOSED layer=M5 d_um=1.536 added=133
  OBS
    LAYER RVTN ;
     RECT  2.16 2.16 84.24 2.295 ;
     RECT  2.16 2.565 84.24 2.835 ;
     RECT  2.16 3.105 84.24 3.375 ;
     RECT  2.16 3.645 84.24 3.915 ;
     RECT  2.16 4.185 84.24 4.455 ;
     RECT  2.16 4.725 84.24 4.995 ;
     RECT  2.16 5.265 84.24 5.535 ;
     RECT  2.16 5.805 84.24 6.075 ;
     RECT  2.16 6.345 84.24 6.615 ;
     RECT  2.16 6.885 84.24 7.155 ;
     RECT  2.16 7.425 84.24 7.695 ;
     RECT  2.16 7.965 84.24 8.235 ;
     RECT  2.16 8.505 84.24 8.775 ;
     RECT  2.16 9.045 84.24 9.315 ;
     RECT  2.16 9.585 84.24 9.855 ;
     RECT  2.16 10.125 84.24 10.395 ;
     RECT  2.16 10.665 84.24 10.935 ;
     RECT  2.16 11.205 84.24 11.475 ;
     RECT  2.16 11.745 84.24 12.015 ;
     RECT  2.16 12.285 84.24 12.555 ;
     RECT  2.16 12.825 84.24 13.095 ;
     RECT  2.16 13.365 84.24 13.635 ;
     RECT  2.16 13.905 84.24 14.175 ;
     RECT  2.16 14.445 84.24 14.715 ;
     RECT  2.16 14.985 84.24 15.255 ;
     RECT  2.16 15.525 84.24 15.795 ;
     RECT  2.16 16.065 84.24 16.335 ;
     RECT  2.16 16.605 84.24 16.875 ;
     RECT  2.16 17.145 84.24 17.415 ;
     RECT  2.16 17.685 84.24 17.955 ;
     RECT  2.16 18.225 84.24 18.495 ;
     RECT  2.16 18.765 84.24 19.035 ;
     RECT  2.16 19.305 84.24 19.575 ;
     RECT  2.16 19.845 84.24 20.115 ;
     RECT  2.16 20.385 84.24 20.655 ;
     RECT  2.16 20.925 84.24 21.195 ;
     RECT  2.16 21.465 84.24 21.735 ;
     RECT  2.16 22.005 84.24 22.275 ;
     RECT  2.16 22.545 84.24 22.815 ;
     RECT  2.16 23.085 84.24 23.355 ;
     RECT  2.16 23.625 84.24 23.895 ;
     RECT  2.16 24.165 84.24 24.435 ;
     RECT  2.16 24.705 84.24 24.975 ;
     RECT  2.16 25.245 84.24 25.515 ;
     RECT  2.16 25.785 84.24 26.055 ;
     RECT  2.16 26.325 84.24 26.595 ;
     RECT  2.16 26.865 84.24 27.135 ;
     RECT  2.16 27.405 84.24 27.675 ;
     RECT  2.16 27.945 84.24 28.215 ;
     RECT  2.16 28.485 84.24 28.755 ;
     RECT  2.16 29.025 84.24 29.295 ;
     RECT  2.16 29.565 84.24 29.835 ;
     RECT  2.16 30.105 84.24 30.375 ;
     RECT  2.16 30.645 84.24 30.915 ;
     RECT  2.16 31.185 84.24 31.455 ;
     RECT  2.16 31.725 84.24 31.995 ;
     RECT  2.16 32.265 84.24 32.535 ;
     RECT  2.16 32.805 84.24 33.075 ;
     RECT  2.16 33.345 84.24 33.615 ;
     RECT  2.16 33.885 84.24 34.155 ;
     RECT  2.16 34.425 84.24 34.695 ;
     RECT  2.16 34.965 84.24 35.235 ;
     RECT  2.16 35.505 84.24 35.775 ;
     RECT  2.16 36.045 84.24 36.315 ;
     RECT  2.16 36.585 84.24 36.855 ;
     RECT  2.16 37.125 84.24 37.395 ;
     RECT  2.16 37.665 84.24 37.935 ;
     RECT  2.16 38.205 84.24 38.475 ;
     RECT  2.16 38.745 84.24 39.015 ;
     RECT  2.16 39.285 84.24 39.555 ;
     RECT  2.16 39.825 84.24 40.095 ;
     RECT  2.16 40.365 84.24 40.635 ;
     RECT  2.16 40.905 84.24 41.175 ;
     RECT  2.16 41.445 84.24 41.715 ;
     RECT  2.16 41.985 84.24 42.255 ;
     RECT  2.16 42.525 84.24 42.795 ;
     RECT  2.16 43.065 84.24 43.335 ;
     RECT  2.16 43.605 84.24 43.875 ;
     RECT  2.16 44.145 84.24 44.415 ;
     RECT  2.16 44.685 84.24 44.955 ;
     RECT  2.16 45.225 84.24 45.495 ;
     RECT  2.16 45.765 84.24 46.035 ;
     RECT  2.16 46.305 84.24 46.575 ;
     RECT  2.16 46.845 84.24 47.115 ;
     RECT  2.16 47.385 84.24 47.655 ;
     RECT  2.16 47.925 84.24 48.195 ;
     RECT  2.16 48.465 84.24 48.735 ;
     RECT  2.16 49.005 84.24 49.275 ;
     RECT  2.16 49.545 84.24 49.815 ;
     RECT  2.16 50.085 84.24 50.355 ;
     RECT  2.16 50.625 84.24 50.895 ;
     RECT  2.16 51.165 84.24 51.435 ;
     RECT  2.16 51.705 84.24 51.975 ;
     RECT  2.16 52.245 84.24 52.515 ;
     RECT  2.16 52.785 84.24 53.055 ;
     RECT  2.16 53.325 84.24 53.595 ;
     RECT  2.16 53.865 84.24 54.135 ;
     RECT  2.16 54.405 84.24 54.675 ;
     RECT  2.16 54.945 84.24 55.215 ;
     RECT  2.16 55.485 84.24 55.755 ;
     RECT  2.16 56.025 84.24 56.295 ;
     RECT  2.16 56.565 84.24 56.835 ;
     RECT  2.16 57.105 84.24 57.375 ;
     RECT  2.16 57.645 84.24 57.915 ;
     RECT  2.16 58.185 84.24 58.455 ;
     RECT  2.16 58.725 84.24 58.995 ;
     RECT  2.16 59.265 84.24 59.535 ;
     RECT  2.16 59.805 84.24 60.075 ;
     RECT  2.16 60.345 84.24 60.615 ;
     RECT  2.16 60.885 84.24 61.155 ;
     RECT  2.16 61.425 84.24 61.695 ;
     RECT  2.16 61.965 84.24 62.235 ;
     RECT  2.16 62.505 84.24 62.775 ;
     RECT  2.16 63.045 84.24 63.315 ;
     RECT  2.16 63.585 84.24 63.855 ;
     RECT  2.16 64.125 84.24 64.395 ;
     RECT  2.16 64.665 84.24 64.935 ;
     RECT  2.16 65.205 84.24 65.475 ;
     RECT  2.16 65.745 84.24 66.015 ;
     RECT  2.16 66.285 84.24 66.555 ;
     RECT  2.16 66.825 84.24 67.095 ;
     RECT  2.16 67.365 84.24 67.635 ;
     RECT  2.16 67.905 84.24 68.175 ;
     RECT  2.16 68.445 84.24 68.715 ;
     RECT  2.16 68.985 84.24 69.255 ;
     RECT  2.16 69.525 84.24 69.795 ;
     RECT  2.16 70.065 84.24 70.335 ;
     RECT  2.16 70.605 84.24 70.875 ;
     RECT  2.16 71.145 84.24 71.415 ;
     RECT  2.16 71.685 84.24 71.955 ;
     RECT  2.16 72.225 84.24 72.495 ;
     RECT  2.16 72.765 84.24 73.035 ;
     RECT  2.16 73.305 84.24 73.575 ;
     RECT  2.16 73.845 84.24 74.115 ;
     RECT  2.16 74.385 84.24 74.655 ;
     RECT  2.16 74.925 84.24 75.195 ;
     RECT  2.16 75.465 84.24 75.735 ;
     RECT  2.16 76.005 84.24 76.275 ;
     RECT  2.16 76.545 84.24 76.815 ;
     RECT  2.16 77.085 84.24 77.355 ;
     RECT  2.16 77.625 84.24 77.895 ;
     RECT  2.16 78.165 84.24 78.435 ;
     RECT  2.16 78.705 84.24 78.975 ;
     RECT  2.16 79.245 84.24 79.515 ;
     RECT  2.16 79.785 84.24 80.055 ;
     RECT  2.16 80.325 84.24 80.595 ;
     RECT  2.16 80.865 84.24 81.135 ;
     RECT  2.16 81.405 84.24 81.675 ;
     RECT  2.16 81.945 84.24 82.215 ;
     RECT  2.16 82.485 84.24 82.755 ;
     RECT  2.16 83.025 84.24 83.295 ;
     RECT  2.16 83.565 84.24 83.835 ;
     RECT  2.16 84.105 84.24 84.24 ;
    LAYER RVTP ;
     RECT  2.16 2.295 84.24 2.565 ;
     RECT  2.16 2.835 84.24 3.105 ;
     RECT  2.16 3.375 84.24 3.645 ;
     RECT  2.16 3.915 84.24 4.185 ;
     RECT  2.16 4.455 84.24 4.725 ;
     RECT  2.16 4.995 84.24 5.265 ;
     RECT  2.16 5.535 84.24 5.805 ;
     RECT  2.16 6.075 84.24 6.345 ;
     RECT  2.16 6.615 84.24 6.885 ;
     RECT  2.16 7.155 84.24 7.425 ;
     RECT  2.16 7.695 84.24 7.965 ;
     RECT  2.16 8.235 84.24 8.505 ;
     RECT  2.16 8.775 84.24 9.045 ;
     RECT  2.16 9.315 84.24 9.585 ;
     RECT  2.16 9.855 84.24 10.125 ;
     RECT  2.16 10.395 84.24 10.665 ;
     RECT  2.16 10.935 84.24 11.205 ;
     RECT  2.16 11.475 84.24 11.745 ;
     RECT  2.16 12.015 84.24 12.285 ;
     RECT  2.16 12.555 84.24 12.825 ;
     RECT  2.16 13.095 84.24 13.365 ;
     RECT  2.16 13.635 84.24 13.905 ;
     RECT  2.16 14.175 84.24 14.445 ;
     RECT  2.16 14.715 84.24 14.985 ;
     RECT  2.16 15.255 84.24 15.525 ;
     RECT  2.16 15.795 84.24 16.065 ;
     RECT  2.16 16.335 84.24 16.605 ;
     RECT  2.16 16.875 84.24 17.145 ;
     RECT  2.16 17.415 84.24 17.685 ;
     RECT  2.16 17.955 84.24 18.225 ;
     RECT  2.16 18.495 84.24 18.765 ;
     RECT  2.16 19.035 84.24 19.305 ;
     RECT  2.16 19.575 84.24 19.845 ;
     RECT  2.16 20.115 84.24 20.385 ;
     RECT  2.16 20.655 84.24 20.925 ;
     RECT  2.16 21.195 84.24 21.465 ;
     RECT  2.16 21.735 84.24 22.005 ;
     RECT  2.16 22.275 84.24 22.545 ;
     RECT  2.16 22.815 84.24 23.085 ;
     RECT  2.16 23.355 84.24 23.625 ;
     RECT  2.16 23.895 84.24 24.165 ;
     RECT  2.16 24.435 84.24 24.705 ;
     RECT  2.16 24.975 84.24 25.245 ;
     RECT  2.16 25.515 84.24 25.785 ;
     RECT  2.16 26.055 84.24 26.325 ;
     RECT  2.16 26.595 84.24 26.865 ;
     RECT  2.16 27.135 84.24 27.405 ;
     RECT  2.16 27.675 84.24 27.945 ;
     RECT  2.16 28.215 84.24 28.485 ;
     RECT  2.16 28.755 84.24 29.025 ;
     RECT  2.16 29.295 84.24 29.565 ;
     RECT  2.16 29.835 84.24 30.105 ;
     RECT  2.16 30.375 84.24 30.645 ;
     RECT  2.16 30.915 84.24 31.185 ;
     RECT  2.16 31.455 84.24 31.725 ;
     RECT  2.16 31.995 84.24 32.265 ;
     RECT  2.16 32.535 84.24 32.805 ;
     RECT  2.16 33.075 84.24 33.345 ;
     RECT  2.16 33.615 84.24 33.885 ;
     RECT  2.16 34.155 84.24 34.425 ;
     RECT  2.16 34.695 84.24 34.965 ;
     RECT  2.16 35.235 84.24 35.505 ;
     RECT  2.16 35.775 84.24 36.045 ;
     RECT  2.16 36.315 84.24 36.585 ;
     RECT  2.16 36.855 84.24 37.125 ;
     RECT  2.16 37.395 84.24 37.665 ;
     RECT  2.16 37.935 84.24 38.205 ;
     RECT  2.16 38.475 84.24 38.745 ;
     RECT  2.16 39.015 84.24 39.285 ;
     RECT  2.16 39.555 84.24 39.825 ;
     RECT  2.16 40.095 84.24 40.365 ;
     RECT  2.16 40.635 84.24 40.905 ;
     RECT  2.16 41.175 84.24 41.445 ;
     RECT  2.16 41.715 84.24 41.985 ;
     RECT  2.16 42.255 84.24 42.525 ;
     RECT  2.16 42.795 84.24 43.065 ;
     RECT  2.16 43.335 84.24 43.605 ;
     RECT  2.16 43.875 84.24 44.145 ;
     RECT  2.16 44.415 84.24 44.685 ;
     RECT  2.16 44.955 84.24 45.225 ;
     RECT  2.16 45.495 84.24 45.765 ;
     RECT  2.16 46.035 84.24 46.305 ;
     RECT  2.16 46.575 84.24 46.845 ;
     RECT  2.16 47.115 84.24 47.385 ;
     RECT  2.16 47.655 84.24 47.925 ;
     RECT  2.16 48.195 84.24 48.465 ;
     RECT  2.16 48.735 84.24 49.005 ;
     RECT  2.16 49.275 84.24 49.545 ;
     RECT  2.16 49.815 84.24 50.085 ;
     RECT  2.16 50.355 84.24 50.625 ;
     RECT  2.16 50.895 84.24 51.165 ;
     RECT  2.16 51.435 84.24 51.705 ;
     RECT  2.16 51.975 84.24 52.245 ;
     RECT  2.16 52.515 84.24 52.785 ;
     RECT  2.16 53.055 84.24 53.325 ;
     RECT  2.16 53.595 84.24 53.865 ;
     RECT  2.16 54.135 84.24 54.405 ;
     RECT  2.16 54.675 84.24 54.945 ;
     RECT  2.16 55.215 84.24 55.485 ;
     RECT  2.16 55.755 84.24 56.025 ;
     RECT  2.16 56.295 84.24 56.565 ;
     RECT  2.16 56.835 84.24 57.105 ;
     RECT  2.16 57.375 84.24 57.645 ;
     RECT  2.16 57.915 84.24 58.185 ;
     RECT  2.16 58.455 84.24 58.725 ;
     RECT  2.16 58.995 84.24 59.265 ;
     RECT  2.16 59.535 84.24 59.805 ;
     RECT  2.16 60.075 84.24 60.345 ;
     RECT  2.16 60.615 84.24 60.885 ;
     RECT  2.16 61.155 84.24 61.425 ;
     RECT  2.16 61.695 84.24 61.965 ;
     RECT  2.16 62.235 84.24 62.505 ;
     RECT  2.16 62.775 84.24 63.045 ;
     RECT  2.16 63.315 84.24 63.585 ;
     RECT  2.16 63.855 84.24 64.125 ;
     RECT  2.16 64.395 84.24 64.665 ;
     RECT  2.16 64.935 84.24 65.205 ;
     RECT  2.16 65.475 84.24 65.745 ;
     RECT  2.16 66.015 84.24 66.285 ;
     RECT  2.16 66.555 84.24 66.825 ;
     RECT  2.16 67.095 84.24 67.365 ;
     RECT  2.16 67.635 84.24 67.905 ;
     RECT  2.16 68.175 84.24 68.445 ;
     RECT  2.16 68.715 84.24 68.985 ;
     RECT  2.16 69.255 84.24 69.525 ;
     RECT  2.16 69.795 84.24 70.065 ;
     RECT  2.16 70.335 84.24 70.605 ;
     RECT  2.16 70.875 84.24 71.145 ;
     RECT  2.16 71.415 84.24 71.685 ;
     RECT  2.16 71.955 84.24 72.225 ;
     RECT  2.16 72.495 84.24 72.765 ;
     RECT  2.16 73.035 84.24 73.305 ;
     RECT  2.16 73.575 84.24 73.845 ;
     RECT  2.16 74.115 84.24 74.385 ;
     RECT  2.16 74.655 84.24 74.925 ;
     RECT  2.16 75.195 84.24 75.465 ;
     RECT  2.16 75.735 84.24 76.005 ;
     RECT  2.16 76.275 84.24 76.545 ;
     RECT  2.16 76.815 84.24 77.085 ;
     RECT  2.16 77.355 84.24 77.625 ;
     RECT  2.16 77.895 84.24 78.165 ;
     RECT  2.16 78.435 84.24 78.705 ;
     RECT  2.16 78.975 84.24 79.245 ;
     RECT  2.16 79.515 84.24 79.785 ;
     RECT  2.16 80.055 84.24 80.325 ;
     RECT  2.16 80.595 84.24 80.865 ;
     RECT  2.16 81.135 84.24 81.405 ;
     RECT  2.16 81.675 84.24 81.945 ;
     RECT  2.16 82.215 84.24 82.485 ;
     RECT  2.16 82.755 84.24 83.025 ;
     RECT  2.16 83.295 84.24 83.565 ;
     RECT  2.16 83.835 84.24 84.105 ;
    LAYER M1 ;
     RECT  2.16 2.151 84.24 84.249 ;
    LAYER M2 ;
     RECT  0.031 30.726 0.131 30.744 ;
     RECT  0.139 25.722 2.16 25.74 ;
     RECT  0.283 51.606 2.16 51.624 ;
     RECT  0.031 54.882 2.16 54.9 ;
     RECT  2.16 2.151 28.867 84.249 ;
     RECT  28.867 2.151 30.803 84.366 ;
     RECT  30.803 2.151 32.071 84.294 ;
     RECT  32.071 2.151 33.395 84.366 ;
     RECT  33.395 2.151 42.763 84.249 ;
     RECT  42.763 2.151 45.031 84.294 ;
     RECT  45.031 2.151 49.207 84.366 ;
     RECT  49.207 2.151 49.631 84.402 ;
     RECT  49.631 2.151 50.935 84.249 ;
     RECT  50.935 2.151 52.115 84.294 ;
     RECT  52.115 2.151 54.715 84.249 ;
     RECT  54.715 2.151 56.011 84.33 ;
     RECT  56.011 2.151 60.827 84.366 ;
     RECT  60.827 2.151 62.699 84.294 ;
     RECT  62.699 2.151 84.24 84.249 ;
     RECT  84.24 30.996 84.335 34.524 ;
     RECT  84.335 30.996 84.371 31.824 ;
     RECT  84.24 51.714 84.875 54.504 ;
     RECT  84.335 33.048 84.911 34.524 ;
     RECT  84.875 51.714 84.983 54.324 ;
     RECT  84.24 55.656 85.451 56.052 ;
     RECT  84.911 33.048 85.487 34.344 ;
     RECT  84.983 51.786 85.487 54.324 ;
     RECT  84.371 30.996 85.523 31.644 ;
     RECT  84.24 48.906 85.523 50.382 ;
     RECT  85.487 53.874 85.523 53.892 ;
     RECT  85.523 31.266 85.559 31.644 ;
     RECT  85.523 49.356 85.595 50.382 ;
     RECT  85.595 49.356 85.631 49.536 ;
     RECT  84.24 35.406 86.243 36.234 ;
     RECT  85.595 50.364 86.251 50.382 ;
     RECT  85.487 33.048 86.279 33.606 ;
     RECT  85.559 31.266 86.315 31.284 ;
     RECT  86.279 33.048 86.315 33.066 ;
     RECT  86.243 35.406 86.315 35.424 ;
     RECT  85.631 49.356 86.315 49.374 ;
     RECT  85.487 51.786 86.315 52.434 ;
     RECT  85.451 55.926 86.315 56.052 ;
     RECT  86.251 50.364 86.351 50.769 ;
     RECT  84.24 30.186 86.387 30.204 ;
     RECT  86.243 36.216 86.387 36.234 ;
     RECT  86.315 56.034 86.387 56.052 ;
    LAYER M3 ;
     RECT  42.732 0.091 42.75 1.723 ;
     RECT  42.732 1.723 43.146 2.191 ;
     RECT  42.732 2.191 43.218 2.263 ;
     RECT  2.415 2.143 2.505 2.413 ;
     RECT  7.815 2.143 7.905 2.413 ;
     RECT  13.215 2.143 13.305 2.413 ;
     RECT  18.615 2.143 18.705 2.413 ;
     RECT  24.015 2.143 24.105 2.413 ;
     RECT  29.415 2.143 29.505 2.413 ;
     RECT  34.815 2.143 34.905 2.413 ;
     RECT  40.215 2.143 40.305 2.413 ;
     RECT  45.615 2.143 45.705 2.413 ;
     RECT  51.015 2.143 51.105 2.413 ;
     RECT  56.415 2.143 56.505 2.413 ;
     RECT  61.815 2.143 61.905 2.413 ;
     RECT  67.215 2.143 67.305 2.413 ;
     RECT  72.615 2.143 72.705 2.413 ;
     RECT  78.015 2.143 78.105 2.413 ;
     RECT  83.415 2.143 83.505 2.413 ;
     RECT  42.732 2.263 43.614 2.569 ;
     RECT  42.372 2.569 43.614 2.759 ;
     RECT  42.948 2.759 43.614 2.803 ;
     RECT  42.948 2.803 43.866 3.379 ;
     RECT  42.948 3.379 43.938 3.721 ;
     RECT  42.444 3.721 44.262 3.875 ;
     RECT  42.444 3.875 43.182 3.947 ;
     RECT  43.92 3.875 44.262 3.947 ;
     RECT  0.108 25.483 0.126 25.579 ;
     RECT  47.664 3.181 47.682 25.681 ;
     RECT  83.415 2.413 83.697 30.145 ;
     RECT  56.415 2.413 56.697 30.271 ;
     RECT  83.415 30.145 83.862 30.451 ;
     RECT  0.108 25.579 0.306 30.721 ;
     RECT  82.728 30.451 83.862 31.261 ;
     RECT  86.364 30.181 86.382 31.261 ;
     RECT  56.415 30.271 57.114 31.387 ;
     RECT  78.015 2.413 78.297 31.387 ;
     RECT  82.656 31.261 83.862 31.495 ;
     RECT  82.656 31.495 83.898 31.531 ;
     RECT  78.015 31.387 78.678 31.559 ;
     RECT  85.5 30.991 85.518 31.621 ;
     RECT  82.656 31.531 84.114 31.801 ;
     RECT  82.656 31.801 84.366 32.431 ;
     RECT  56.415 31.387 57.762 32.467 ;
     RECT  85.5 31.621 85.554 32.491 ;
     RECT  86.292 31.261 86.382 32.491 ;
     RECT  85.5 32.491 86.382 32.525 ;
     RECT  59.688 32.161 59.706 32.701 ;
     RECT  61.815 2.413 62.097 32.737 ;
     RECT  78.015 31.559 78.297 32.737 ;
     RECT  85.5 32.525 86.31 32.813 ;
     RECT  78.015 32.737 78.75 32.837 ;
     RECT  82.476 32.431 84.366 32.881 ;
     RECT  81.468 32.881 81.486 33.071 ;
     RECT  85.5 32.813 85.554 33.101 ;
     RECT  82.332 32.881 84.366 33.115 ;
     RECT  82.044 33.115 84.366 33.197 ;
     RECT  85.464 33.349 85.482 33.355 ;
     RECT  82.044 33.197 83.79 33.539 ;
     RECT  86.292 32.813 86.31 33.583 ;
     RECT  84.852 33.355 85.482 33.989 ;
     RECT  47.664 25.681 48.006 34.051 ;
     RECT  82.152 33.539 83.79 34.079 ;
     RECT  82.224 34.079 83.79 34.465 ;
     RECT  86.256 33.583 86.31 34.507 ;
     RECT  84.888 33.989 85.482 34.529 ;
     RECT  78.015 32.837 78.297 34.663 ;
     RECT  86.22 34.507 86.31 34.699 ;
     RECT  78.015 34.663 78.678 34.763 ;
     RECT  82.224 34.465 83.934 35.041 ;
     RECT  81.792 35.041 83.934 35.159 ;
     RECT  45.615 2.413 45.897 35.401 ;
     RECT  85.464 34.529 85.482 35.699 ;
     RECT  86.22 34.699 86.382 35.969 ;
     RECT  81.792 35.159 83.862 35.977 ;
     RECT  81.648 35.977 83.862 36.121 ;
     RECT  86.364 35.969 86.382 36.239 ;
     RECT  81.576 36.121 83.862 36.275 ;
     RECT  78.015 34.763 78.297 36.481 ;
     RECT  81.576 36.275 83.697 36.509 ;
     RECT  78.015 36.481 78.678 36.617 ;
     RECT  38.16 44.851 38.178 45.005 ;
     RECT  38.592 45.031 38.61 45.341 ;
     RECT  81.576 36.509 81.81 48.775 ;
     RECT  82.836 36.509 83.697 48.775 ;
     RECT  81.576 48.775 83.697 48.811 ;
     RECT  81.576 48.811 83.79 49.171 ;
     RECT  85.5 48.901 85.518 49.513 ;
     RECT  86.292 49.351 86.31 49.513 ;
     RECT  81.576 49.171 83.898 49.621 ;
     RECT  51.015 2.413 51.297 49.711 ;
     RECT  61.452 32.737 62.097 49.981 ;
     RECT  64.26 48.361 64.278 50.287 ;
     RECT  78.015 36.617 78.297 50.287 ;
     RECT  85.5 49.513 86.31 50.359 ;
     RECT  78.015 50.287 78.75 50.387 ;
     RECT  78.015 50.387 78.678 50.459 ;
     RECT  85.5 50.359 86.346 50.774 ;
     RECT  45.615 35.401 46.242 50.791 ;
     RECT  64.26 50.287 64.314 50.791 ;
     RECT  81.576 49.621 84.042 50.819 ;
     RECT  78.015 50.459 78.297 51.439 ;
     RECT  64.26 50.791 64.35 51.511 ;
     RECT  78.015 51.439 78.678 51.511 ;
     RECT  0.036 30.721 0.306 51.629 ;
     RECT  47.664 34.051 48.078 51.637 ;
     RECT  48.888 34.663 48.906 51.637 ;
     RECT  81.576 50.819 84.006 51.637 ;
     RECT  45.615 50.791 46.314 51.673 ;
     RECT  78.015 51.511 78.75 51.701 ;
     RECT  85.5 50.774 86.31 51.709 ;
     RECT  43.92 3.947 43.938 51.781 ;
     RECT  81.036 51.637 84.006 51.809 ;
     RECT  84.96 51.709 86.31 51.821 ;
     RECT  56.415 32.467 58.446 51.871 ;
     RECT  67.215 2.413 67.497 51.871 ;
     RECT  78.015 51.701 78.678 51.871 ;
     RECT  56.304 51.871 58.446 51.917 ;
     RECT  67.104 51.871 67.497 51.917 ;
     RECT  77.904 51.871 78.678 51.917 ;
     RECT  81.288 51.809 84.006 51.917 ;
     RECT  86.256 51.821 86.31 51.917 ;
     RECT  81.576 51.917 84.006 52.051 ;
     RECT  84.96 51.821 85.482 52.051 ;
     RECT  81.576 52.051 85.482 52.109 ;
     RECT  55.008 35.131 55.026 52.141 ;
     RECT  64.26 51.511 64.602 52.177 ;
     RECT  78.015 51.917 78.678 52.277 ;
     RECT  43.848 51.781 43.938 52.285 ;
     RECT  43.488 52.285 43.938 52.439 ;
     RECT  86.292 51.917 86.31 52.493 ;
     RECT  43.848 52.439 43.938 52.555 ;
     RECT  43.848 52.555 44.478 52.583 ;
     RECT  81.576 52.109 84.006 52.589 ;
     RECT  84.888 52.109 85.482 52.651 ;
     RECT  59.688 32.701 60.246 53.221 ;
     RECT  61.452 49.981 62.298 53.221 ;
     RECT  81.576 52.589 83.697 53.323 ;
     RECT  84.888 52.651 85.518 53.323 ;
     RECT  81.576 53.323 85.518 53.429 ;
     RECT  55.008 52.141 55.53 53.527 ;
     RECT  47.664 51.637 48.906 53.563 ;
     RECT  84.816 53.429 85.518 53.897 ;
     RECT  84.816 53.897 85.482 54.329 ;
     RECT  86.292 54.187 86.31 54.379 ;
     RECT  84.816 54.329 85.446 54.437 ;
     RECT  81.576 53.429 83.898 54.445 ;
     RECT  86.256 54.379 86.31 54.475 ;
     RECT  84.852 54.437 85.446 54.509 ;
     RECT  86.256 54.475 86.382 54.509 ;
     RECT  78.015 52.277 78.297 54.607 ;
     RECT  78.015 54.607 78.678 54.707 ;
     RECT  44.46 52.583 44.478 54.715 ;
     RECT  44.46 54.715 44.55 54.743 ;
     RECT  50.868 49.711 51.297 54.743 ;
     RECT  54.468 53.527 55.53 54.743 ;
     RECT  81.576 54.445 83.934 54.751 ;
     RECT  45.432 51.673 46.314 54.841 ;
     RECT  59.688 53.221 62.298 54.841 ;
     RECT  0.036 51.629 0.054 54.905 ;
     RECT  45.432 54.841 46.53 54.985 ;
     RECT  47.52 53.563 48.906 54.985 ;
     RECT  81.468 54.751 83.934 55.111 ;
     RECT  52.308 36.517 52.326 55.381 ;
     RECT  85.428 54.509 85.446 55.679 ;
     RECT  37.62 55.687 37.638 55.723 ;
     RECT  34.815 2.413 35.097 55.795 ;
     RECT  37.224 55.723 37.998 55.795 ;
     RECT  40.215 2.413 40.497 55.795 ;
     RECT  31.32 55.795 31.338 55.831 ;
     RECT  34.815 55.795 35.694 55.831 ;
     RECT  37.224 55.795 38.718 55.831 ;
     RECT  40.215 55.795 41.022 55.831 ;
     RECT  40.215 55.831 41.094 55.921 ;
     RECT  42.444 3.947 42.462 55.921 ;
     RECT  86.292 54.509 86.382 55.949 ;
     RECT  31.32 55.831 31.554 55.957 ;
     RECT  32.292 55.831 32.31 55.957 ;
     RECT  34.815 55.831 38.826 55.957 ;
     RECT  44.532 54.743 44.55 55.957 ;
     RECT  45.432 54.985 48.906 55.957 ;
     RECT  78.015 54.707 78.297 55.957 ;
     RECT  34.776 55.957 38.826 56.029 ;
     RECT  44.532 55.957 48.906 56.029 ;
     RECT  78.015 55.957 78.678 56.057 ;
     RECT  86.364 55.949 86.382 56.057 ;
     RECT  34.776 56.029 38.898 56.101 ;
     RECT  40.14 55.921 41.094 56.101 ;
     RECT  26.784 56.101 27.738 56.141 ;
     RECT  34.776 56.101 39.078 56.191 ;
     RECT  40.104 56.101 41.094 56.191 ;
     RECT  42.444 55.921 42.642 56.191 ;
     RECT  44.46 56.029 48.906 56.219 ;
     RECT  81.468 55.111 84.042 56.219 ;
     RECT  30.924 55.957 32.778 56.227 ;
     RECT  30.924 56.227 33.066 56.299 ;
     RECT  29.415 2.413 29.697 56.335 ;
     RECT  34.776 56.191 42.642 56.347 ;
     RECT  81.468 56.219 83.934 56.399 ;
     RECT  29.415 56.335 29.934 56.461 ;
     RECT  30.924 56.299 33.246 56.461 ;
     RECT  34.56 56.347 42.642 56.497 ;
     RECT  34.524 56.497 42.642 56.533 ;
     RECT  30.852 56.461 33.246 56.569 ;
     RECT  34.488 56.533 42.642 56.605 ;
     RECT  29.268 56.461 29.934 56.641 ;
     RECT  30.852 56.569 33.678 56.641 ;
     RECT  34.488 56.605 42.75 56.641 ;
     RECT  44.46 56.219 48.834 56.731 ;
     RECT  81.468 56.399 83.898 56.759 ;
     RECT  54.576 54.743 55.53 56.767 ;
     RECT  56.415 51.917 58.446 56.767 ;
     RECT  26.856 56.141 27.738 56.839 ;
     RECT  26.856 56.839 28.026 56.875 ;
     RECT  29.268 56.641 29.97 56.875 ;
     RECT  54.576 56.767 58.446 56.875 ;
     RECT  59.184 54.841 62.298 56.875 ;
     RECT  26.532 56.875 28.026 56.911 ;
     RECT  28.764 56.875 29.97 56.911 ;
     RECT  30.852 56.641 42.75 56.911 ;
     RECT  30.852 56.911 43.11 57.001 ;
     RECT  43.884 56.731 48.834 57.001 ;
     RECT  49.68 31.621 49.698 57.001 ;
     RECT  63.396 50.323 63.414 57.001 ;
     RECT  63.108 57.001 63.414 57.019 ;
     RECT  26.46 56.911 29.97 57.037 ;
     RECT  30.852 57.001 49.698 57.037 ;
     RECT  50.94 54.743 51.297 57.037 ;
     RECT  26.46 57.037 49.698 57.073 ;
     RECT  54.576 56.875 62.298 57.109 ;
     RECT  63.072 57.019 63.414 57.109 ;
     RECT  52.308 55.381 52.83 57.115 ;
     RECT  67.215 51.917 67.497 57.163 ;
     RECT  78.015 56.057 78.297 57.163 ;
     RECT  26.208 57.073 49.698 57.181 ;
     RECT  54.576 57.109 63.414 57.181 ;
     RECT  67.104 57.163 67.497 57.209 ;
     RECT  77.904 57.163 78.297 57.209 ;
     RECT  54.324 57.181 63.414 57.299 ;
     RECT  74.664 57.181 74.682 57.299 ;
     RECT  50.796 57.037 51.297 57.343 ;
     RECT  50.616 57.343 51.297 57.355 ;
     RECT  52.308 57.115 53.046 57.415 ;
     RECT  54.324 57.299 62.154 57.415 ;
     RECT  54.252 57.415 62.154 57.437 ;
     RECT  25.776 57.181 49.698 57.451 ;
     RECT  52.308 57.415 53.082 57.451 ;
     RECT  62.964 57.299 63.414 57.451 ;
     RECT  64.152 52.177 64.602 57.451 ;
     RECT  25.092 57.451 49.698 57.569 ;
     RECT  52.308 57.451 53.19 57.577 ;
     RECT  54.252 57.437 62.097 57.577 ;
     RECT  50.508 57.355 51.297 57.721 ;
     RECT  52.308 57.577 62.097 57.721 ;
     RECT  25.092 57.569 37.17 57.839 ;
     RECT  62.964 57.451 64.602 57.839 ;
     RECT  38.016 57.569 49.698 57.955 ;
     RECT  50.508 57.721 62.097 57.955 ;
     RECT  38.016 57.955 62.097 58.019 ;
     RECT  26.028 57.839 37.17 58.351 ;
     RECT  38.016 58.019 40.662 58.351 ;
     RECT  24.015 2.413 24.297 58.621 ;
     RECT  25.092 57.839 25.11 58.621 ;
     RECT  41.616 58.019 62.097 58.621 ;
     RECT  63.036 57.839 64.602 58.621 ;
     RECT  24.015 58.621 25.11 58.693 ;
     RECT  26.028 58.351 40.662 58.693 ;
     RECT  24.015 58.693 40.662 58.801 ;
     RECT  41.616 58.621 64.602 58.801 ;
     RECT  24.015 58.801 64.602 60.413 ;
     RECT  24.015 60.413 41.13 60.547 ;
     RECT  81.468 56.759 83.697 60.809 ;
     RECT  23.976 60.547 41.13 61.159 ;
     RECT  41.868 60.413 64.602 61.159 ;
     RECT  81.576 60.809 83.697 61.619 ;
     RECT  23.976 61.159 64.602 61.763 ;
     RECT  29.415 61.763 64.602 62.005 ;
     RECT  23.976 61.763 28.638 62.491 ;
     RECT  29.415 62.005 64.962 62.491 ;
     RECT  23.976 62.491 64.962 62.581 ;
     RECT  65.844 62.311 65.862 62.581 ;
     RECT  23.976 62.581 65.862 62.609 ;
     RECT  81.792 61.619 83.697 62.609 ;
     RECT  67.215 57.209 67.497 62.707 ;
     RECT  81.792 62.609 82.53 62.843 ;
     RECT  66.636 62.707 67.497 62.851 ;
     RECT  81.792 62.843 82.098 62.879 ;
     RECT  66.6 62.851 67.497 63.239 ;
     RECT  23.976 62.609 65.79 63.391 ;
     RECT  23.976 63.391 66.114 63.815 ;
     RECT  24.015 63.815 66.114 64.363 ;
     RECT  67.104 63.239 67.497 64.363 ;
     RECT  24.015 64.363 67.497 64.411 ;
     RECT  24.015 64.411 67.914 64.867 ;
     RECT  23.472 64.867 68.346 65.273 ;
     RECT  23.472 65.273 66.186 65.281 ;
     RECT  66.96 65.273 68.346 65.543 ;
     RECT  23.4 65.281 66.186 65.551 ;
     RECT  23.112 65.551 66.186 65.705 ;
     RECT  23.112 65.705 65.862 65.821 ;
     RECT  22.752 65.821 65.862 66.019 ;
     RECT  66.96 65.543 67.986 66.091 ;
     RECT  66.924 66.091 67.986 66.181 ;
     RECT  22.284 66.019 65.862 66.325 ;
     RECT  66.744 66.181 67.986 66.487 ;
     RECT  21.96 66.325 65.862 66.865 ;
     RECT  66.672 66.487 67.986 66.865 ;
     RECT  21.96 66.865 67.986 67.261 ;
     RECT  21.348 67.261 67.986 67.435 ;
     RECT  21.06 67.435 67.986 67.559 ;
     RECT  21.348 67.559 67.986 67.981 ;
     RECT  21.348 67.981 68.382 68.521 ;
     RECT  21.348 68.521 68.67 68.768 ;
     RECT  21.168 68.768 68.67 68.909 ;
     RECT  21.168 68.909 39.474 69.061 ;
     RECT  40.215 68.909 68.67 69.629 ;
     RECT  81.792 62.879 81.81 69.629 ;
     RECT  20.448 69.061 39.474 69.871 ;
     RECT  40.215 69.629 68.634 69.871 ;
     RECT  20.448 69.871 68.634 69.989 ;
     RECT  20.448 69.989 68.526 70.025 ;
     RECT  20.448 70.025 68.238 70.069 ;
     RECT  20.376 70.069 68.238 70.303 ;
     RECT  18.615 2.413 18.897 70.645 ;
     RECT  20.016 70.303 68.238 70.645 ;
     RECT  18.615 70.645 68.238 70.771 ;
     RECT  18.252 70.771 68.238 70.807 ;
     RECT  17.676 70.807 68.238 70.835 ;
     RECT  17.676 70.835 68.13 71.105 ;
     RECT  17.676 71.105 22.986 71.117 ;
     RECT  23.724 71.105 68.13 71.689 ;
     RECT  23.724 71.689 68.598 71.761 ;
     RECT  16.524 71.761 17.478 71.923 ;
     RECT  18.252 71.117 22.986 71.923 ;
     RECT  23.724 71.761 68.634 71.923 ;
     RECT  23.724 71.923 68.958 72.419 ;
     RECT  23.724 72.419 68.886 72.455 ;
     RECT  16.524 71.923 22.986 72.697 ;
     RECT  23.724 72.455 68.634 72.697 ;
     RECT  16.524 72.697 68.634 72.959 ;
     RECT  17.1 72.959 68.634 73.535 ;
     RECT  17.892 73.535 68.454 74.317 ;
     RECT  17.892 74.317 68.49 74.461 ;
     RECT  17.1 73.535 17.118 74.587 ;
     RECT  17.892 74.461 68.958 74.587 ;
     RECT  17.1 74.587 68.958 75.271 ;
     RECT  17.1 75.271 69.03 75.425 ;
     RECT  44.1 75.425 69.03 75.497 ;
     RECT  44.244 75.497 69.03 75.569 ;
     RECT  17.1 75.425 43.362 75.631 ;
     RECT  66.168 75.569 69.03 75.929 ;
     RECT  66.168 75.929 68.886 75.965 ;
     RECT  16.992 75.631 43.362 76.045 ;
     RECT  16.452 76.045 43.362 76.253 ;
     RECT  16.632 76.253 43.362 76.279 ;
     RECT  44.244 75.569 64.818 76.351 ;
     RECT  16.632 76.279 43.434 76.379 ;
     RECT  44.244 76.351 64.854 76.459 ;
     RECT  21.456 76.379 43.434 76.477 ;
     RECT  44.244 76.459 65.034 76.477 ;
     RECT  66.168 75.965 68.454 76.504 ;
     RECT  21.456 76.477 65.394 76.549 ;
     RECT  66.132 76.504 68.454 76.549 ;
     RECT  21.456 76.549 68.454 76.613 ;
     RECT  21.456 76.613 68.202 76.775 ;
     RECT  59.832 76.775 68.202 76.925 ;
     RECT  60.084 76.925 68.202 77.081 ;
     RECT  16.632 76.379 20.682 77.161 ;
     RECT  21.456 76.775 59.094 77.161 ;
     RECT  16.632 77.161 59.094 77.585 ;
     RECT  60.084 77.081 68.094 77.791 ;
     RECT  60.012 77.791 68.094 77.963 ;
     RECT  16.92 77.585 59.094 77.971 ;
     RECT  60.012 77.963 65.25 77.971 ;
     RECT  16.92 77.971 65.25 78.089 ;
     RECT  16.92 78.089 58.95 78.475 ;
     RECT  16.632 78.475 58.95 78.629 ;
     RECT  59.688 78.089 65.25 78.745 ;
     RECT  66.096 77.963 68.094 78.745 ;
     RECT  17.424 78.629 58.95 78.935 ;
     RECT  18.108 78.935 58.95 79.051 ;
     RECT  59.688 78.745 68.094 79.051 ;
     RECT  18.108 79.051 68.094 80.519 ;
     RECT  66.06 80.519 68.094 80.825 ;
     RECT  18.108 80.519 65.322 81.059 ;
     RECT  20.448 81.059 65.322 81.409 ;
     RECT  66.06 80.825 66.258 81.409 ;
     RECT  20.448 81.409 66.258 81.707 ;
     RECT  18.108 81.059 19.602 81.743 ;
     RECT  18.18 81.743 19.602 81.905 ;
     RECT  20.448 81.707 66.078 82.219 ;
     RECT  20.34 82.219 66.078 82.409 ;
     RECT  18.615 81.905 19.602 82.417 ;
     RECT  20.34 82.409 65.826 82.417 ;
     RECT  67.215 80.825 68.094 82.445 ;
     RECT  18.615 82.417 65.826 82.679 ;
     RECT  21.672 82.679 65.826 82.859 ;
     RECT  18.615 82.679 20.934 83.129 ;
     RECT  21.672 82.859 65.682 83.255 ;
     RECT  18.615 83.129 19.602 83.525 ;
     RECT  21.672 83.255 23.238 83.525 ;
     RECT  20.592 83.129 20.934 83.561 ;
     RECT  24.015 83.255 64.926 83.669 ;
     RECT  20.592 83.561 20.754 83.759 ;
     RECT  21.78 83.525 23.238 83.759 ;
     RECT  28.872 83.669 64.926 83.759 ;
     RECT  24.015 83.669 28.134 83.768 ;
     RECT  20.592 83.759 20.61 83.795 ;
     RECT  21.78 83.759 23.094 83.795 ;
     RECT  24.015 83.768 28.098 83.795 ;
     RECT  28.872 83.759 59.886 83.795 ;
     RECT  64.548 83.759 64.926 83.795 ;
     RECT  38.952 83.795 47.682 83.837 ;
     RECT  21.78 83.795 22.878 83.903 ;
     RECT  26.64 83.795 28.098 83.903 ;
     RECT  2.415 2.413 2.697 83.987 ;
     RECT  7.815 2.413 8.097 83.987 ;
     RECT  13.215 2.413 13.497 83.987 ;
     RECT  18.615 83.525 18.897 83.987 ;
     RECT  24.015 83.795 24.297 83.987 ;
     RECT  67.215 82.445 67.497 83.987 ;
     RECT  72.615 2.413 72.897 83.987 ;
     RECT  78.015 57.209 78.297 83.987 ;
     RECT  83.415 62.609 83.697 83.987 ;
     RECT  22.284 83.903 22.878 84.029 ;
     RECT  25.524 83.795 25.65 84.029 ;
     RECT  26.64 83.903 27.81 84.029 ;
     RECT  28.872 83.795 38.07 84.029 ;
     RECT  38.952 83.837 42.03 84.029 ;
     RECT  42.768 83.837 47.682 84.029 ;
     RECT  58.14 83.795 59.634 84.029 ;
     RECT  60.732 83.759 63.81 84.029 ;
     RECT  64.548 83.795 64.89 84.029 ;
     RECT  65.664 83.255 65.682 84.029 ;
     RECT  28.872 84.029 37.314 84.065 ;
     RECT  38.952 84.029 41.31 84.065 ;
     RECT  42.768 84.029 43.182 84.065 ;
     RECT  48.42 83.795 57.222 84.065 ;
     RECT  64.548 84.029 64.746 84.065 ;
     RECT  25.596 84.029 25.65 84.137 ;
     RECT  28.872 84.065 36.342 84.137 ;
     RECT  40.215 84.065 41.31 84.137 ;
     RECT  43.92 84.029 47.502 84.137 ;
     RECT  53.856 84.065 57.15 84.137 ;
     RECT  61.815 84.029 63.81 84.137 ;
     RECT  64.548 84.065 64.566 84.137 ;
     RECT  22.86 84.029 22.878 84.173 ;
     RECT  25.632 84.137 25.65 84.173 ;
     RECT  41.292 84.137 41.31 84.173 ;
     RECT  48.564 84.065 52.974 84.173 ;
     RECT  53.892 84.137 56.97 84.173 ;
     RECT  60.732 84.029 61.038 84.173 ;
     RECT  48.636 84.173 52.974 84.179 ;
     RECT  28.872 84.137 35.91 84.209 ;
     RECT  43.92 84.137 47.322 84.209 ;
     RECT  53.892 84.173 53.982 84.209 ;
     RECT  55.728 84.173 56.97 84.209 ;
     RECT  58.572 84.029 58.59 84.209 ;
     RECT  61.815 84.137 62.694 84.209 ;
     RECT  63.792 84.137 63.81 84.209 ;
     RECT  43.92 84.209 47.142 84.221 ;
     RECT  2.415 83.987 2.505 84.257 ;
     RECT  7.815 83.987 7.905 84.257 ;
     RECT  13.215 83.987 13.305 84.257 ;
     RECT  18.615 83.987 18.705 84.257 ;
     RECT  24.015 83.987 24.105 84.257 ;
     RECT  28.872 84.209 35.226 84.257 ;
     RECT  40.215 84.137 40.305 84.257 ;
     RECT  55.728 84.209 56.505 84.257 ;
     RECT  61.815 84.209 61.905 84.257 ;
     RECT  67.215 83.987 67.305 84.257 ;
     RECT  72.615 83.987 72.705 84.257 ;
     RECT  78.015 83.987 78.105 84.257 ;
     RECT  83.415 83.987 83.505 84.257 ;
     RECT  30.168 84.257 35.226 84.299 ;
     RECT  42.768 84.065 43.038 84.299 ;
     RECT  48.636 84.179 51.21 84.299 ;
     RECT  52.092 84.179 52.974 84.299 ;
     RECT  55.728 84.257 56.034 84.299 ;
     RECT  60.732 84.173 60.822 84.299 ;
     RECT  62.676 84.209 62.694 84.299 ;
     RECT  48.708 84.299 50.274 84.317 ;
     RECT  54.72 84.173 54.738 84.335 ;
     RECT  59.436 84.029 59.454 84.335 ;
     RECT  44.316 84.221 47.142 84.365 ;
     RECT  53.964 84.209 53.982 84.365 ;
     RECT  28.872 84.257 28.89 84.371 ;
     RECT  44.388 84.365 47.142 84.371 ;
     RECT  48.708 84.317 50.202 84.371 ;
     RECT  56.016 84.299 56.034 84.371 ;
     RECT  60.804 84.299 60.822 84.371 ;
     RECT  44.388 84.371 44.442 84.413 ;
     RECT  51.192 84.299 51.21 84.413 ;
     RECT  48.996 84.371 50.202 84.941 ;
     RECT  30.78 84.299 35.226 84.989 ;
     RECT  30.78 84.989 32.598 85.517 ;
     RECT  45.432 84.371 47.142 85.517 ;
     RECT  30.888 85.517 32.598 85.565 ;
     RECT  44.424 84.413 44.442 85.565 ;
     RECT  26.64 84.029 27.774 86.189 ;
     RECT  33.732 84.989 35.226 86.237 ;
     RECT  30.996 85.565 32.598 86.285 ;
     RECT  33.84 86.237 34.974 86.285 ;
     RECT  46.008 85.517 46.962 86.285 ;
     RECT  49.176 84.941 50.202 86.285 ;
     RECT  26.64 86.189 27.09 86.333 ;
     RECT  30.996 86.285 31.77 86.333 ;
     RECT  50.184 86.285 50.202 86.333 ;
     RECT  52.308 84.299 52.974 86.333 ;
     RECT  26.64 86.333 26.658 86.381 ;
     RECT  31.176 86.333 31.77 86.381 ;
     RECT  39.312 84.065 39.33 86.381 ;
     RECT  43.02 84.299 43.038 86.381 ;
     RECT  46.872 86.285 46.89 86.381 ;
     RECT  49.248 86.285 49.266 86.381 ;
     RECT  52.308 86.333 52.326 86.381 ;
    LAYER M4 ;
     RECT  0.06 25.392 0.173 25.704 ;
     RECT  0.173 25.392 0.227 25.608 ;
     RECT  0.227 25.584 0.317 25.608 ;
     RECT  0.181 63.072 2.408 63.096 ;
     RECT  2.408 2.148 2.512 84.252 ;
     RECT  2.512 2.418 2.704 83.982 ;
     RECT  2.704 63.072 7.808 63.096 ;
     RECT  7.808 2.148 7.912 84.252 ;
     RECT  7.912 2.418 8.104 83.982 ;
     RECT  8.104 63.072 13.208 63.096 ;
     RECT  13.208 2.148 13.312 84.252 ;
     RECT  13.312 2.418 13.504 83.982 ;
     RECT  16.441 76.224 17.269 76.248 ;
     RECT  17.197 75.168 17.809 75.192 ;
     RECT  17.809 74.688 17.893 75.192 ;
     RECT  17.269 76.224 18.169 76.92 ;
     RECT  16.513 72.912 18.277 72.936 ;
     RECT  16.621 78.48 18.421 78.504 ;
     RECT  13.504 63.072 18.608 63.096 ;
     RECT  17.917 71.088 18.608 71.112 ;
     RECT  18.277 72.816 18.608 72.936 ;
     RECT  17.893 74.496 18.608 75.192 ;
     RECT  18.169 76.224 18.608 77.064 ;
     RECT  18.421 78.384 18.608 78.504 ;
     RECT  18.385 79.728 18.608 79.752 ;
     RECT  18.169 81.456 18.608 81.48 ;
     RECT  18.608 2.148 18.712 84.252 ;
     RECT  18.712 2.418 18.904 83.982 ;
     RECT  18.904 74.448 19.145 78.408 ;
     RECT  19.145 74.448 19.433 78.168 ;
     RECT  19.433 74.448 19.468 77.256 ;
     RECT  19.468 74.688 19.613 77.256 ;
     RECT  18.904 79.728 19.619 81.528 ;
     RECT  19.619 79.728 19.649 81.24 ;
     RECT  19.613 74.688 20.189 74.952 ;
     RECT  18.904 83.184 20.329 83.208 ;
     RECT  20.341 70.08 20.428 70.104 ;
     RECT  18.904 71.088 20.581 71.832 ;
     RECT  18.904 72.816 20.581 72.84 ;
     RECT  20.501 78.672 20.585 78.696 ;
     RECT  19.649 81.216 20.585 81.24 ;
     RECT  20.329 82.224 20.621 83.208 ;
     RECT  19.649 79.728 20.729 79.992 ;
     RECT  19.613 76.32 20.761 77.256 ;
     RECT  20.761 76.176 20.801 77.256 ;
     RECT  20.581 71.088 20.941 72.84 ;
     RECT  20.801 76.176 21.049 76.2 ;
     RECT  20.801 77.232 21.233 77.256 ;
     RECT  20.941 71.088 21.265 72.936 ;
     RECT  20.189 74.688 21.373 74.76 ;
     RECT  21.265 70.704 21.521 72.936 ;
     RECT  20.729 79.968 21.553 79.992 ;
     RECT  21.373 74.496 21.589 74.76 ;
     RECT  21.049 75.984 21.589 76.2 ;
     RECT  20.621 82.416 21.589 83.208 ;
     RECT  21.589 82.128 21.617 83.208 ;
     RECT  21.589 74.496 21.635 76.2 ;
     RECT  21.635 75.216 21.665 76.2 ;
     RECT  21.617 82.128 21.701 83.256 ;
     RECT  21.521 71.616 21.841 72.936 ;
     RECT  21.701 82.128 21.917 82.44 ;
     RECT  21.049 67.44 21.949 67.464 ;
     RECT  21.265 78.624 22.097 78.648 ;
     RECT  21.665 75.216 22.313 76.008 ;
     RECT  21.949 66.672 22.345 67.464 ;
     RECT  21.553 79.968 22.421 80.328 ;
     RECT  21.157 68.784 22.453 68.808 ;
     RECT  22.453 68.784 22.457 69.048 ;
     RECT  22.313 75.216 22.597 75.24 ;
     RECT  21.841 71.616 22.601 73.32 ;
     RECT  21.917 82.128 22.781 82.152 ;
     RECT  22.597 74.688 22.837 75.24 ;
     RECT  22.837 73.92 22.883 75.24 ;
     RECT  22.883 73.92 22.924 73.944 ;
     RECT  22.601 71.616 22.925 72.936 ;
     RECT  22.925 71.616 23.065 72.84 ;
     RECT  22.345 66.672 23.125 67.752 ;
     RECT  22.457 69.024 23.269 69.048 ;
     RECT  22.883 75.12 23.893 75.24 ;
     RECT  18.904 63.072 24.008 63.096 ;
     RECT  23.125 64.896 24.008 67.752 ;
     RECT  23.269 69.024 24.008 69.528 ;
     RECT  23.065 70.656 24.008 72.84 ;
     RECT  23.893 74.592 24.008 75.24 ;
     RECT  22.705 76.752 24.008 76.776 ;
     RECT  23.569 78.624 24.008 78.648 ;
     RECT  22.421 79.968 24.008 80.28 ;
     RECT  23.653 81.456 24.008 81.48 ;
     RECT  23.641 82.656 24.008 82.68 ;
     RECT  24.008 2.148 24.112 84.252 ;
     RECT  24.112 2.418 24.304 83.982 ;
     RECT  24.304 76.608 24.515 78.648 ;
     RECT  24.304 69.648 24.545 73.32 ;
     RECT  24.515 77.328 24.545 78.648 ;
     RECT  24.304 81.984 24.977 82.008 ;
     RECT  24.545 77.328 25.013 77.448 ;
     RECT  24.545 69.648 25.091 72.264 ;
     RECT  24.304 80.112 25.121 80.136 ;
     RECT  24.304 58.128 25.129 58.776 ;
     RECT  24.304 66.816 25.129 68.376 ;
     RECT  25.013 77.424 25.409 77.448 ;
     RECT  24.304 83.232 25.477 83.256 ;
     RECT  24.304 75.12 25.481 75.144 ;
     RECT  24.304 62.592 25.58 63.864 ;
     RECT  24.545 78.624 25.589 78.648 ;
     RECT  25.58 62.592 25.613 64.2 ;
     RECT  24.304 65.52 25.613 65.736 ;
     RECT  25.613 62.592 25.657 65.736 ;
     RECT  25.129 66.816 25.657 67.992 ;
     RECT  25.369 79.776 25.667 79.8 ;
     RECT  25.657 62.592 25.805 67.992 ;
     RECT  25.091 70.128 25.805 72.264 ;
     RECT  24.545 73.296 25.813 73.32 ;
     RECT  25.477 82.224 25.873 83.256 ;
     RECT  25.813 73.296 25.9 74.088 ;
     RECT  25.805 62.592 25.909 63.864 ;
     RECT  25.873 82.224 25.985 83.64 ;
     RECT  25.129 58.128 26.093 58.68 ;
     RECT  25.621 80.784 26.125 80.808 ;
     RECT  25.801 75.216 26.161 75.288 ;
     RECT  26.053 76.32 26.161 76.344 ;
     RECT  25.985 83.136 26.201 83.64 ;
     RECT  26.093 58.128 26.593 58.152 ;
     RECT  26.161 75.216 26.669 76.344 ;
     RECT  26.669 76.32 26.737 76.344 ;
     RECT  26.201 83.136 26.741 83.256 ;
     RECT  26.125 80.784 26.773 80.952 ;
     RECT  25.909 62.4 26.777 63.864 ;
     RECT  26.616 82.032 26.819 82.056 ;
     RECT  25.805 70.704 26.849 72.264 ;
     RECT  26.773 56.112 26.857 56.136 ;
     RECT  26.773 79.104 26.857 80.952 ;
     RECT  25.9 73.296 26.881 73.944 ;
     RECT  26.669 75.216 26.881 75.24 ;
     RECT  26.629 86.352 27.061 86.376 ;
     RECT  26.881 73.296 27.245 75.24 ;
     RECT  26.737 76.32 27.313 76.632 ;
     RECT  26.773 77.712 27.313 77.736 ;
     RECT  25.805 65.52 27.317 67.992 ;
     RECT  26.857 79.968 27.317 80.952 ;
     RECT  27.313 76.32 27.353 77.736 ;
     RECT  27.317 66.048 27.389 67.992 ;
     RECT  26.593 58.08 27.421 58.152 ;
     RECT  24.304 60.816 27.445 60.84 ;
     RECT  26.777 62.592 27.461 63.864 ;
     RECT  27.445 60 27.491 60.84 ;
     RECT  27.245 74.592 27.53 75.24 ;
     RECT  27.491 60 27.532 60.408 ;
     RECT  27.421 58.08 27.601 58.68 ;
     RECT  26.849 71.616 27.673 72.264 ;
     RECT  27.245 73.296 27.673 73.368 ;
     RECT  26.741 83.136 27.709 83.16 ;
     RECT  27.673 71.616 27.713 73.368 ;
     RECT  27.061 86.304 27.745 86.376 ;
     RECT  27.317 80.256 28.037 80.952 ;
     RECT  28.037 80.304 28.361 80.952 ;
     RECT  27.389 66.048 28.465 67.8 ;
     RECT  28.033 68.976 28.465 69 ;
     RECT  27.353 76.32 28.465 77.592 ;
     RECT  28.465 66.048 28.501 69 ;
     RECT  27.601 58.08 28.508 59.304 ;
     RECT  27.53 74.592 28.537 75.192 ;
     RECT  28.465 76.32 28.537 77.928 ;
     RECT  28.361 80.4 28.573 80.952 ;
     RECT  27.532 60.384 28.717 60.408 ;
     RECT  27.713 71.616 28.717 73.32 ;
     RECT  27.461 62.592 28.748 63.672 ;
     RECT  28.508 57.6 28.753 59.304 ;
     RECT  28.717 60.384 28.753 61.368 ;
     RECT  27.709 83.136 29.041 83.736 ;
     RECT  28.748 62.592 29.257 63.816 ;
     RECT  28.717 71.616 29.257 73.368 ;
     RECT  28.549 56.496 29.408 56.52 ;
     RECT  28.753 57.6 29.408 61.368 ;
     RECT  29.257 62.496 29.408 63.816 ;
     RECT  28.501 65.424 29.408 69 ;
     RECT  28.429 70.08 29.408 70.104 ;
     RECT  29.257 71.616 29.408 73.56 ;
     RECT  28.537 74.592 29.408 77.928 ;
     RECT  28.573 80.4 29.408 81.624 ;
     RECT  29.041 83.136 29.408 83.784 ;
     RECT  29.408 2.148 29.512 84.252 ;
     RECT  29.512 2.418 29.704 83.982 ;
     RECT  29.704 62.496 29.765 70.104 ;
     RECT  29.704 82.272 29.801 83.784 ;
     RECT  29.704 71.184 29.873 74.76 ;
     RECT  29.873 71.184 30.161 73.656 ;
     RECT  29.765 62.832 30.277 70.104 ;
     RECT  30.277 66.24 30.697 70.104 ;
     RECT  30.161 71.184 30.697 72.264 ;
     RECT  29.704 77.904 30.697 78.648 ;
     RECT  29.704 61.344 30.769 61.368 ;
     RECT  29.873 74.736 30.769 74.76 ;
     RECT  29.704 75.84 30.769 76.344 ;
     RECT  29.704 80.64 30.769 80.664 ;
     RECT  27.745 86.16 30.769 86.376 ;
     RECT  29.704 58.656 30.805 59.496 ;
     RECT  30.769 61.296 30.805 61.416 ;
     RECT  30.769 80.64 30.805 81.048 ;
     RECT  29.801 82.56 30.805 83.784 ;
     RECT  30.161 73.296 30.809 73.656 ;
     RECT  30.697 77.376 30.841 78.648 ;
     RECT  30.769 74.736 30.853 76.344 ;
     RECT  30.697 66.24 30.995 72.264 ;
     RECT  30.805 80.4 30.997 81.048 ;
     RECT  29.704 56.496 31.025 56.52 ;
     RECT  30.997 79.968 31.061 81.048 ;
     RECT  30.805 82.56 31.133 84.12 ;
     RECT  31.061 79.968 31.205 80.664 ;
     RECT  31.133 82.56 31.285 83.208 ;
     RECT  31.285 82.512 31.331 83.208 ;
     RECT  30.805 58.656 31.381 61.416 ;
     RECT  31.331 82.512 31.385 82.536 ;
     RECT  31.381 58.128 31.421 61.416 ;
     RECT  30.277 62.832 31.421 65.16 ;
     RECT  31.421 59.472 31.453 61.416 ;
     RECT  31.421 62.832 31.453 64.392 ;
     RECT  31.453 59.472 31.457 64.392 ;
     RECT  30.995 66.24 31.457 68.088 ;
     RECT  30.841 77.376 31.484 78.744 ;
     RECT  31.205 79.968 31.484 80.472 ;
     RECT  31.421 58.128 31.669 58.152 ;
     RECT  30.853 74.736 31.705 74.808 ;
     RECT  30.853 75.792 31.777 76.344 ;
     RECT  30.995 69.504 31.885 72.264 ;
     RECT  30.809 73.296 31.885 73.512 ;
     RECT  31.777 75.792 31.907 76.392 ;
     RECT  31.484 77.376 31.925 80.472 ;
     RECT  31.457 59.472 32.033 64.2 ;
     RECT  31.885 69.504 32.033 73.512 ;
     RECT  31.907 76.32 32.033 76.392 ;
     RECT  31.457 66.24 32.281 67.8 ;
     RECT  32.033 69.504 32.285 70.248 ;
     RECT  31.925 79.152 32.285 80.472 ;
     RECT  32.173 84.336 32.353 84.36 ;
     RECT  31.705 74.544 32.357 74.808 ;
     RECT  31.925 77.376 32.357 78.168 ;
     RECT  32.285 70.128 32.465 70.248 ;
     RECT  32.033 59.472 32.531 60.84 ;
     RECT  32.357 74.544 32.533 74.664 ;
     RECT  32.533 74.496 32.537 74.664 ;
     RECT  31.669 57.312 32.569 58.152 ;
     RECT  32.531 59.472 32.569 59.88 ;
     RECT  32.285 79.584 32.573 80.472 ;
     RECT  32.033 71.328 32.641 73.512 ;
     RECT  32.537 74.496 32.641 74.616 ;
     RECT  32.465 70.128 32.681 70.152 ;
     RECT  32.569 57.312 32.713 59.88 ;
     RECT  32.281 65.856 32.713 67.8 ;
     RECT  32.641 71.328 32.717 74.616 ;
     RECT  30.769 85.488 32.819 86.376 ;
     RECT  32.033 76.32 32.929 76.344 ;
     RECT  32.353 84.192 33.001 84.36 ;
     RECT  32.033 61.872 33.037 64.2 ;
     RECT  32.929 75.648 33.037 76.344 ;
     RECT  33.001 84.192 33.203 84.984 ;
     RECT  32.713 65.856 33.325 68.904 ;
     RECT  32.573 79.68 33.325 80.472 ;
     RECT  32.636 81.456 33.325 81.48 ;
     RECT  33.037 61.056 33.397 64.2 ;
     RECT  33.203 84.192 33.433 84.36 ;
     RECT  33.325 79.68 33.491 81.48 ;
     RECT  33.433 83.808 33.517 84.36 ;
     RECT  33.325 65.856 33.541 69 ;
     RECT  33.397 61.056 33.577 64.44 ;
     RECT  33.541 65.424 33.577 69 ;
     RECT  33.491 79.68 33.577 80.616 ;
     RECT  33.577 61.056 33.589 69 ;
     RECT  33.517 84.192 33.617 84.36 ;
     RECT  33.589 61.056 33.635 69.048 ;
     RECT  32.717 71.328 33.649 74.568 ;
     RECT  32.713 56.592 33.689 59.88 ;
     RECT  33.635 68.688 33.721 69.048 ;
     RECT  33.649 70.8 33.721 74.568 ;
     RECT  33.635 66.816 33.725 67.656 ;
     RECT  32.357 77.904 33.788 78.168 ;
     RECT  33.577 79.488 33.788 80.616 ;
     RECT  33.721 68.688 33.793 74.568 ;
     RECT  33.635 61.056 33.827 65.448 ;
     RECT  33.037 75.648 33.829 76.92 ;
     RECT  33.788 77.904 33.829 80.616 ;
     RECT  32.819 86.208 33.98 86.376 ;
     RECT  33.617 84.288 34.013 84.36 ;
     RECT  33.98 85.392 34.156 86.376 ;
     RECT  33.793 68.688 34.172 74.616 ;
     RECT  33.829 75.648 34.172 80.616 ;
     RECT  33.827 61.056 34.261 63.576 ;
     RECT  32.713 82.656 34.369 82.68 ;
     RECT  33.689 57.408 34.441 59.88 ;
     RECT  34.261 60.96 34.441 63.576 ;
     RECT  34.156 85.488 34.451 86.376 ;
     RECT  33.827 65.232 34.693 65.448 ;
     RECT  33.725 66.816 34.693 67.56 ;
     RECT  34.549 56.352 34.765 56.376 ;
     RECT  34.441 57.408 34.765 63.576 ;
     RECT  34.369 82.656 34.801 82.776 ;
     RECT  34.765 56.352 34.808 63.576 ;
     RECT  34.693 65.232 34.808 67.56 ;
     RECT  34.172 68.688 34.808 80.616 ;
     RECT  34.801 82.656 34.808 82.968 ;
     RECT  34.808 2.148 34.912 84.252 ;
     RECT  34.912 2.418 35.104 83.982 ;
     RECT  35.104 76.176 35.165 78.648 ;
     RECT  34.451 86.208 35.237 86.376 ;
     RECT  35.104 68.352 35.273 69 ;
     RECT  35.273 68.352 35.363 68.952 ;
     RECT  35.165 76.176 35.363 76.728 ;
     RECT  35.104 58.656 35.452 63.768 ;
     RECT  35.104 55.92 35.699 57.672 ;
     RECT  35.165 77.712 35.741 78.648 ;
     RECT  35.104 81.456 35.747 83.304 ;
     RECT  35.747 81.984 35.777 83.304 ;
     RECT  35.104 64.944 35.891 66.84 ;
     RECT  35.363 76.176 35.921 76.344 ;
     RECT  35.363 68.352 36.097 68.376 ;
     RECT  35.891 66.72 36.133 66.84 ;
     RECT  36.097 67.968 36.133 68.376 ;
     RECT  36.133 66.72 36.137 68.376 ;
     RECT  35.104 79.68 36.137 80.424 ;
     RECT  35.699 57.072 36.169 57.672 ;
     RECT  35.452 58.656 36.169 60.36 ;
     RECT  35.104 69.984 36.179 74.616 ;
     RECT  36.137 66.768 36.245 68.376 ;
     RECT  35.452 61.68 36.38 63.768 ;
     RECT  36.38 61.68 36.467 63.816 ;
     RECT  36.245 66.816 36.529 68.376 ;
     RECT  35.777 81.984 36.569 82.008 ;
     RECT  36.169 57.072 36.572 60.36 ;
     RECT  36.572 57.072 36.605 61.224 ;
     RECT  36.605 58.464 36.659 61.224 ;
     RECT  36.179 71.328 36.749 74.616 ;
     RECT  35.699 55.92 36.925 55.944 ;
     RECT  36.605 57.072 36.925 57.48 ;
     RECT  36.749 71.328 36.937 73.512 ;
     RECT  35.777 83.28 36.961 83.304 ;
     RECT  36.659 58.464 37.001 59.784 ;
     RECT  36.179 69.984 37.109 70.104 ;
     RECT  36.467 62.208 37.139 63.384 ;
     RECT  36.137 79.68 37.141 79.752 ;
     RECT  37.001 58.464 37.181 59.544 ;
     RECT  36.961 83.28 37.217 83.784 ;
     RECT  35.921 76.224 37.244 76.344 ;
     RECT  37.244 76.08 37.285 76.344 ;
     RECT  36.659 61.2 37.361 61.224 ;
     RECT  35.741 77.712 37.433 77.928 ;
     RECT  36.529 66.816 37.573 68.904 ;
     RECT  36.997 74.736 37.573 74.76 ;
     RECT  37.285 75.792 37.573 76.344 ;
     RECT  37.109 70.032 37.577 70.104 ;
     RECT  36.937 73.248 37.813 73.512 ;
     RECT  37.573 74.736 37.813 76.344 ;
     RECT  37.813 73.248 37.865 76.344 ;
     RECT  37.865 73.248 37.9 74.328 ;
     RECT  37.573 66.72 37.933 68.904 ;
     RECT  37.577 70.08 38.009 70.104 ;
     RECT  36.937 71.328 38.009 72.264 ;
     RECT  37.9 73.248 38.117 73.512 ;
     RECT  36.925 55.92 38.149 57.48 ;
     RECT  37.181 58.608 38.149 59.544 ;
     RECT  38.149 55.92 38.195 59.544 ;
     RECT  37.141 79.152 38.221 79.752 ;
     RECT  37.933 66.72 38.293 69 ;
     RECT  37.433 77.904 38.341 77.928 ;
     RECT  38.221 79.152 38.341 80.232 ;
     RECT  38.341 77.904 38.397 80.664 ;
     RECT  35.891 64.944 38.401 64.968 ;
     RECT  37.217 83.76 38.405 83.784 ;
     RECT  38.396 60.24 38.483 60.264 ;
     RECT  38.149 44.976 38.54 45 ;
     RECT  38.397 79.728 38.54 80.664 ;
     RECT  38.54 44.976 38.581 45.336 ;
     RECT  37.865 75.408 38.581 76.344 ;
     RECT  38.401 64.944 38.617 65.448 ;
     RECT  38.293 66.72 38.617 69.048 ;
     RECT  38.365 61.44 38.621 61.464 ;
     RECT  38.581 44.688 38.627 45.336 ;
     RECT  38.195 55.92 38.627 59.256 ;
     RECT  38.617 64.944 38.657 69.048 ;
     RECT  38.581 75.408 38.693 76.728 ;
     RECT  38.693 75.408 38.837 76.344 ;
     RECT  37.609 82.608 38.837 82.632 ;
     RECT  38.627 56.352 38.909 59.256 ;
     RECT  38.54 79.728 38.917 81.048 ;
     RECT  38.917 79.728 39.053 81.528 ;
     RECT  39.053 79.728 39.059 80.664 ;
     RECT  37.139 62.448 39.161 63.384 ;
     RECT  35.237 86.352 39.341 86.376 ;
     RECT  38.397 77.904 39.625 78.648 ;
     RECT  39.644 71.232 39.685 71.256 ;
     RECT  38.009 72.24 39.685 72.264 ;
     RECT  38.837 76.32 39.805 76.344 ;
     RECT  39.625 77.664 39.805 78.648 ;
     RECT  39.805 76.32 39.932 78.648 ;
     RECT  38.627 44.688 40.208 44.712 ;
     RECT  38.909 56.496 40.208 59.256 ;
     RECT  39.161 62.544 40.208 63.384 ;
     RECT  38.657 64.944 40.208 69 ;
     RECT  39.685 71.232 40.208 72.264 ;
     RECT  38.117 73.248 40.208 73.368 ;
     RECT  39.973 74.64 40.208 74.664 ;
     RECT  39.932 75.888 40.208 78.648 ;
     RECT  39.059 79.776 40.208 80.664 ;
     RECT  39.301 82.128 40.208 82.152 ;
     RECT  40.208 2.148 40.312 84.252 ;
     RECT  40.312 2.418 40.504 83.982 ;
     RECT  40.504 65.472 40.565 68.424 ;
     RECT  40.504 73.248 40.565 74.664 ;
     RECT  40.504 79.776 40.601 80.376 ;
     RECT  40.504 56.496 40.739 58.68 ;
     RECT  40.739 56.64 41.177 58.68 ;
     RECT  40.504 60.528 41.213 63.384 ;
     RECT  40.504 70.08 41.497 70.104 ;
     RECT  41.497 64.368 41.603 64.392 ;
     RECT  40.504 76.32 41.605 78.696 ;
     RECT  40.601 80.352 41.605 80.376 ;
     RECT  41.605 76.32 41.709 80.376 ;
     RECT  41.709 76.32 41.753 79.608 ;
     RECT  40.565 73.248 41.929 73.944 ;
     RECT  40.504 81.744 41.929 81.768 ;
     RECT  41.213 62.112 41.965 63.384 ;
     RECT  41.753 76.32 41.969 79.176 ;
     RECT  41.177 56.736 41.996 58.68 ;
     RECT  41.929 73.248 42.001 74.568 ;
     RECT  41.213 60.528 42.037 60.984 ;
     RECT  41.965 62.112 42.041 63.48 ;
     RECT  41.996 56.736 42.083 59.064 ;
     RECT  42.037 60.384 42.253 60.984 ;
     RECT  42.083 56.736 42.257 58.68 ;
     RECT  40.565 65.472 42.289 67.704 ;
     RECT  42.257 57.024 42.293 58.68 ;
     RECT  41.497 70.08 42.293 70.728 ;
     RECT  40.504 83.808 42.293 83.832 ;
     RECT  42.001 73.248 42.325 75.192 ;
     RECT  41.969 76.32 42.325 76.344 ;
     RECT  41.929 80.784 42.325 81.768 ;
     RECT  42.253 59.76 42.437 60.984 ;
     RECT  42.289 64.944 42.757 67.704 ;
     RECT  41.821 68.976 42.757 69 ;
     RECT  42.293 70.08 42.757 70.104 ;
     RECT  42.437 59.76 42.797 59.784 ;
     RECT  42.325 80.784 42.797 82.056 ;
     RECT  42.325 73.248 42.803 76.344 ;
     RECT  42.696 0.096 42.805 0.12 ;
     RECT  42.757 64.944 42.937 67.8 ;
     RECT  42.757 68.976 42.937 70.104 ;
     RECT  42.937 64.944 42.977 70.104 ;
     RECT  40.504 72.24 43.009 72.264 ;
     RECT  42.937 3.696 43.043 3.72 ;
     RECT  40.504 44.688 43.043 44.712 ;
     RECT  42.977 65.904 43.049 70.104 ;
     RECT  43.009 71.328 43.081 72.264 ;
     RECT  42.803 73.248 43.081 74.952 ;
     RECT  42.797 80.784 43.085 81.528 ;
     RECT  42.437 60.96 43.117 60.984 ;
     RECT  43.117 60.96 43.121 61.128 ;
     RECT  42.853 1.728 43.157 1.752 ;
     RECT  42.041 62.976 43.369 63.48 ;
     RECT  43.049 65.904 43.373 69.24 ;
     RECT  43.085 81.504 43.373 81.528 ;
     RECT  43.081 71.328 43.409 74.952 ;
     RECT  42.293 57.12 43.477 58.68 ;
     RECT  43.477 57.12 43.481 58.728 ;
     RECT  43.333 83.232 43.513 83.256 ;
     RECT  42.803 76.32 43.532 76.344 ;
     RECT  41.969 77.568 43.532 79.176 ;
     RECT  43.369 62.976 43.549 63.816 ;
     RECT  43.121 61.104 43.553 61.128 ;
     RECT  43.532 76.32 43.619 79.176 ;
     RECT  43.225 80.352 43.625 80.376 ;
     RECT  43.549 62.112 43.837 63.816 ;
     RECT  43.621 59.952 43.907 59.976 ;
     RECT  43.513 83.232 43.909 83.544 ;
     RECT  43.373 65.904 43.913 66.888 ;
     RECT  43.409 74.688 43.913 74.952 ;
     RECT  43.837 61.584 43.981 63.816 ;
     RECT  43.619 77.52 43.985 79.176 ;
     RECT  43.373 68.352 44.021 69.24 ;
     RECT  43.481 57.312 44.237 58.728 ;
     RECT  43.909 83.232 44.261 84.216 ;
     RECT  44.237 57.408 44.293 58.728 ;
     RECT  44.261 83.232 44.344 84.36 ;
     RECT  43.619 76.32 44.377 76.392 ;
     RECT  43.985 79.152 44.396 79.176 ;
     RECT  44.344 83.232 44.413 84.408 ;
     RECT  43.009 86.352 44.413 86.376 ;
     RECT  44.413 82.56 44.461 84.408 ;
     RECT  43.981 61.584 44.483 63.864 ;
     RECT  44.483 62.976 44.489 63.864 ;
     RECT  43.409 71.328 44.521 73.656 ;
     RECT  44.437 56.064 44.524 56.088 ;
     RECT  44.396 79.152 44.525 79.752 ;
     RECT  44.269 80.784 44.525 81.336 ;
     RECT  43.913 74.928 44.581 74.952 ;
     RECT  44.377 75.936 44.581 76.392 ;
     RECT  44.483 61.584 44.665 61.992 ;
     RECT  44.489 63.072 44.665 63.864 ;
     RECT  43.913 66.288 44.701 66.888 ;
     RECT  44.377 68.112 44.701 68.136 ;
     RECT  44.581 74.928 44.701 76.392 ;
     RECT  44.525 79.2 44.773 79.752 ;
     RECT  44.525 80.784 44.773 80.808 ;
     RECT  44.701 74.928 44.809 76.536 ;
     RECT  43.985 77.52 44.809 77.976 ;
     RECT  44.461 82.56 44.869 83.64 ;
     RECT  44.521 70.56 44.917 73.656 ;
     RECT  44.917 70.56 44.989 73.848 ;
     RECT  44.809 74.928 44.989 77.976 ;
     RECT  44.701 66.288 45.157 68.136 ;
     RECT  44.665 63.072 45.349 64.104 ;
     RECT  44.125 65.232 45.349 65.256 ;
     RECT  44.413 85.536 45.421 86.376 ;
     RECT  45.157 66.288 45.493 68.184 ;
     RECT  44.665 61.008 45.601 61.992 ;
     RECT  45.421 55.968 45.608 55.992 ;
     RECT  44.293 57.408 45.608 58.776 ;
     RECT  45.601 60.384 45.608 61.992 ;
     RECT  45.349 63.072 45.608 65.256 ;
     RECT  45.493 66.24 45.608 68.184 ;
     RECT  44.449 69.504 45.608 69.528 ;
     RECT  44.989 70.56 45.608 77.976 ;
     RECT  44.773 79.2 45.608 80.808 ;
     RECT  44.869 81.984 45.608 83.64 ;
     RECT  45.421 85.488 45.683 86.376 ;
     RECT  45.608 2.148 45.712 84.252 ;
     RECT  45.712 2.418 45.904 84.12 ;
     RECT  45.904 60.384 46.019 63.672 ;
     RECT  45.904 65.232 46.073 69.48 ;
     RECT  45.904 71.136 46.109 84.12 ;
     RECT  46.019 60.96 46.181 63.672 ;
     RECT  46.109 81.984 46.217 84.12 ;
     RECT  46.109 71.136 46.397 80.856 ;
     RECT  45.904 55.152 46.793 55.992 ;
     RECT  46.397 71.136 46.793 78.936 ;
     RECT  45.683 85.536 46.825 86.376 ;
     RECT  46.825 85.488 46.901 86.376 ;
     RECT  46.793 71.136 46.937 73.944 ;
     RECT  46.181 61.968 46.973 63.672 ;
     RECT  46.217 82.176 47.185 82.2 ;
     RECT  46.217 83.616 47.185 84.12 ;
     RECT  46.901 85.488 47.219 86.28 ;
     RECT  45.904 57.12 47.221 57.624 ;
     RECT  45.904 58.752 47.221 58.776 ;
     RECT  46.973 62.208 47.257 63.672 ;
     RECT  46.073 66.192 47.261 69.48 ;
     RECT  46.937 71.472 47.261 73.944 ;
     RECT  47.221 57.12 47.293 58.776 ;
     RECT  46.181 60.96 47.42 60.984 ;
     RECT  47.257 62.208 47.473 64.248 ;
     RECT  47.261 68.352 47.477 69.48 ;
     RECT  47.42 60.96 47.507 61.224 ;
     RECT  47.293 57.024 47.557 58.776 ;
     RECT  47.477 68.352 47.585 69.336 ;
     RECT  47.185 82.176 47.585 84.12 ;
     RECT  46.793 55.152 47.603 55.272 ;
     RECT  47.473 62.208 47.617 64.296 ;
     RECT  47.557 56.256 47.644 58.776 ;
     RECT  46.793 75.168 47.833 78.936 ;
     RECT  46.397 80.016 47.833 80.856 ;
     RECT  47.833 75.168 47.977 80.856 ;
     RECT  47.617 62.208 47.981 64.68 ;
     RECT  47.977 74.592 47.989 80.856 ;
     RECT  47.989 74.592 48.035 80.904 ;
     RECT  48.035 74.592 48.061 77.976 ;
     RECT  47.219 86.064 48.179 86.28 ;
     RECT  47.585 69.312 48.233 69.336 ;
     RECT  47.644 57.024 48.269 58.776 ;
     RECT  48.269 57.168 48.341 58.776 ;
     RECT  47.585 82.176 48.373 82.872 ;
     RECT  47.461 59.856 48.409 59.88 ;
     RECT  48.341 57.216 48.517 58.776 ;
     RECT  48.409 59.76 48.517 59.88 ;
     RECT  48.517 57.216 48.701 59.88 ;
     RECT  48.373 82.08 48.709 82.872 ;
     RECT  47.585 84.048 48.709 84.12 ;
     RECT  47.981 64.368 48.769 64.68 ;
     RECT  48.061 74.688 48.773 77.976 ;
     RECT  47.981 62.208 48.805 63.384 ;
     RECT  47.261 66.192 48.877 66.888 ;
     RECT  47.261 71.472 48.913 73.416 ;
     RECT  48.035 79.2 48.913 80.904 ;
     RECT  48.913 70.56 48.953 73.416 ;
     RECT  48.709 82.08 48.956 84.12 ;
     RECT  48.993 60.96 48.997 60.984 ;
     RECT  48.913 79.2 48.997 80.952 ;
     RECT  48.997 79.2 49.084 81.048 ;
     RECT  48.956 82.08 49.089 84.936 ;
     RECT  48.877 66.192 49.129 67.56 ;
     RECT  48.179 86.208 49.237 86.28 ;
     RECT  48.773 74.688 49.273 76.344 ;
     RECT  49.089 82.08 49.273 84.36 ;
     RECT  48.997 60.96 49.309 61.08 ;
     RECT  49.129 66.192 49.313 67.656 ;
     RECT  49.273 82.032 49.357 84.36 ;
     RECT  49.309 60.912 49.417 61.08 ;
     RECT  48.953 70.56 49.493 70.68 ;
     RECT  48.841 68.976 49.517 69 ;
     RECT  49.517 68.832 49.525 69 ;
     RECT  48.701 57.312 49.561 59.88 ;
     RECT  49.417 60.912 49.561 61.128 ;
     RECT  49.493 70.608 49.573 70.68 ;
     RECT  48.953 71.856 49.597 73.416 ;
     RECT  49.273 74.64 49.597 76.344 ;
     RECT  49.237 86.208 49.597 86.376 ;
     RECT  48.769 64.368 49.669 64.776 ;
     RECT  49.313 66.192 49.669 66.216 ;
     RECT  49.669 64.368 49.756 65.16 ;
     RECT  48.805 62.16 49.777 63.384 ;
     RECT  49.756 64.368 49.777 64.968 ;
     RECT  49.597 85.488 49.811 86.376 ;
     RECT  49.313 67.248 49.885 67.656 ;
     RECT  49.525 68.832 49.885 69.576 ;
     RECT  49.573 70.608 49.925 70.632 ;
     RECT  49.084 79.2 50.348 80.856 ;
     RECT  49.811 86.112 50.387 86.376 ;
     RECT  48.773 77.52 50.533 77.928 ;
     RECT  50.348 79.2 50.533 80.952 ;
     RECT  50.533 77.52 50.581 80.952 ;
     RECT  49.357 82.08 50.581 84.36 ;
     RECT  49.777 62.16 50.821 64.968 ;
     RECT  50.581 77.52 50.917 84.36 ;
     RECT  49.885 67.248 50.929 69.576 ;
     RECT  45.904 51.888 51.008 51.912 ;
     RECT  45.904 52.992 51.008 53.016 ;
     RECT  47.603 55.152 51.008 55.176 ;
     RECT  49.561 57.312 51.008 61.128 ;
     RECT  50.821 62.16 51.008 65.064 ;
     RECT  49.669 66.144 51.008 66.216 ;
     RECT  50.929 67.248 51.008 70.296 ;
     RECT  49.597 71.856 51.008 76.344 ;
     RECT  50.917 77.52 51.008 84.408 ;
     RECT  50.387 86.208 51.059 86.376 ;
     RECT  51.008 2.148 51.112 84.408 ;
     RECT  51.112 2.418 51.221 84.408 ;
     RECT  51.221 2.418 51.304 84.36 ;
     RECT  51.304 70.752 51.797 84.36 ;
     RECT  51.304 67.296 51.869 69.768 ;
     RECT  51.797 70.752 52.163 73.32 ;
     RECT  51.797 74.592 52.163 84.36 ;
     RECT  51.304 57.168 52.229 65.016 ;
     RECT  52.163 71.904 52.229 73.32 ;
     RECT  52.229 60.384 52.273 65.016 ;
     RECT  52.229 71.952 52.301 73.32 ;
     RECT  51.059 86.304 52.337 86.376 ;
     RECT  51.304 66.144 52.405 66.312 ;
     RECT  51.869 67.296 52.405 68.328 ;
     RECT  52.163 77.904 52.409 84.36 ;
     RECT  52.163 74.592 52.481 76.92 ;
     RECT  52.273 60.384 52.553 64.392 ;
     RECT  52.481 75.024 52.625 76.92 ;
     RECT  52.405 66.144 52.739 68.328 ;
     RECT  52.625 75.024 52.877 76.392 ;
     RECT  52.553 60.624 52.913 64.392 ;
     RECT  52.739 66.144 52.981 68.28 ;
     RECT  52.337 86.304 52.985 86.328 ;
     RECT  52.229 57.168 53.017 59.016 ;
     RECT  53.017 57.12 53.057 59.016 ;
     RECT  52.163 70.752 53.093 70.776 ;
     RECT  52.913 60.624 53.165 63.816 ;
     RECT  53.057 58.752 53.197 59.016 ;
     RECT  51.869 69.552 53.233 69.768 ;
     RECT  53.165 60.768 53.315 63.816 ;
     RECT  52.981 66.048 53.561 68.28 ;
     RECT  53.315 61.392 53.633 63.816 ;
     RECT  53.561 68.256 53.633 68.28 ;
     RECT  52.409 82.464 53.773 84.36 ;
     RECT  52.301 71.952 53.845 73.272 ;
     RECT  52.409 77.904 53.881 81.384 ;
     RECT  53.773 82.416 53.881 84.36 ;
     RECT  53.881 77.904 53.885 84.36 ;
     RECT  53.633 62.544 53.989 63.816 ;
     RECT  52.877 75.12 53.989 76.392 ;
     RECT  53.885 79.728 53.993 84.36 ;
     RECT  53.989 62.544 54.061 64.2 ;
     RECT  53.885 77.904 54.097 78.648 ;
     RECT  53.197 58.752 54.133 59.256 ;
     RECT  54.061 62.544 54.173 64.392 ;
     RECT  54.097 77.616 54.229 78.648 ;
     RECT  53.845 71.904 54.325 73.272 ;
     RECT  53.989 74.352 54.325 76.392 ;
     RECT  53.633 61.392 54.385 61.416 ;
     RECT  54.173 63.024 54.389 64.392 ;
     RECT  53.561 66.048 54.425 66.504 ;
     RECT  53.057 57.12 54.457 57.768 ;
     RECT  54.133 58.752 54.457 59.832 ;
     RECT  53.993 79.728 54.533 84.072 ;
     RECT  54.325 71.904 54.601 76.392 ;
     RECT  54.425 66.048 54.637 66.168 ;
     RECT  54.601 71.856 54.641 76.392 ;
     RECT  54.385 61.008 54.713 61.416 ;
     RECT  54.637 64.944 54.713 66.168 ;
     RECT  53.233 69.552 54.745 70.104 ;
     RECT  54.641 71.856 54.749 73.272 ;
     RECT  54.641 74.352 54.781 76.392 ;
     RECT  54.229 77.568 54.781 78.648 ;
     RECT  54.457 57.12 54.857 59.832 ;
     RECT  54.781 74.352 54.961 78.648 ;
     RECT  54.533 79.728 54.961 84.024 ;
     RECT  54.961 74.352 55.001 84.024 ;
     RECT  55.001 74.352 55.073 76.92 ;
     RECT  54.749 71.904 55.109 73.272 ;
     RECT  54.857 57.12 55.177 59.784 ;
     RECT  54.745 69.552 55.213 70.584 ;
     RECT  55.001 77.904 55.217 84.024 ;
     RECT  55.213 68.736 55.325 70.584 ;
     RECT  55.109 71.904 55.325 73.176 ;
     RECT  54.637 67.248 55.537 67.272 ;
     RECT  54.389 63.024 55.669 63.384 ;
     RECT  55.537 67.248 55.669 67.704 ;
     RECT  55.325 68.736 55.669 69.816 ;
     RECT  54.713 66.144 55.676 66.168 ;
     RECT  55.669 67.248 55.676 69.816 ;
     RECT  55.177 57.072 55.681 59.784 ;
     RECT  54.713 61.392 55.781 61.416 ;
     RECT  55.669 63.024 55.781 63.864 ;
     RECT  55.781 61.392 56.185 63.864 ;
     RECT  54.713 64.944 56.185 65.16 ;
     RECT  51.304 51.888 56.408 51.912 ;
     RECT  51.304 52.992 56.408 53.016 ;
     RECT  51.304 55.152 56.408 55.176 ;
     RECT  55.681 57.024 56.408 59.784 ;
     RECT  56.185 61.392 56.408 65.16 ;
     RECT  55.676 66.144 56.408 69.816 ;
     RECT  55.325 71.952 56.408 73.176 ;
     RECT  55.073 74.592 56.408 74.616 ;
     RECT  55.073 76.32 56.408 76.92 ;
     RECT  55.217 77.952 56.408 84.024 ;
     RECT  56.408 2.148 56.512 84.252 ;
     RECT  56.512 2.418 56.704 83.982 ;
     RECT  56.704 79.728 56.765 83.784 ;
     RECT  56.704 75.216 56.881 78.504 ;
     RECT  56.704 62.16 56.909 64.872 ;
     RECT  56.909 62.16 56.945 64.728 ;
     RECT  56.765 80.88 57.089 83.016 ;
     RECT  56.704 57.024 57.233 59.832 ;
     RECT  57.233 59.184 57.341 59.832 ;
     RECT  56.881 75.456 57.733 78.504 ;
     RECT  56.765 79.728 57.733 79.752 ;
     RECT  57.733 75.456 57.781 79.752 ;
     RECT  57.089 80.88 57.781 80.904 ;
     RECT  57.781 75.456 57.868 80.904 ;
     RECT  56.704 66.432 57.881 69.864 ;
     RECT  57.868 75.456 57.881 79.752 ;
     RECT  57.881 75.456 57.989 78.072 ;
     RECT  56.945 62.16 58.021 64.44 ;
     RECT  56.704 71.184 58.057 74.088 ;
     RECT  57.989 75.456 58.057 76.488 ;
     RECT  58.021 61.92 58.061 64.44 ;
     RECT  58.057 71.184 58.061 76.488 ;
     RECT  57.881 66.432 58.117 66.6 ;
     RECT  57.989 77.904 58.133 78.072 ;
     RECT  58.061 62.976 58.277 64.44 ;
     RECT  58.061 71.184 58.349 74.952 ;
     RECT  57.233 57.024 58.453 58.2 ;
     RECT  58.349 71.184 58.457 72.888 ;
     RECT  58.117 66.144 58.529 66.6 ;
     RECT  58.453 56.928 58.561 58.2 ;
     RECT  57.341 59.184 58.561 59.208 ;
     RECT  57.881 67.584 58.561 69.864 ;
     RECT  58.457 71.184 58.561 71.448 ;
     RECT  58.061 61.92 58.597 61.944 ;
     RECT  58.561 56.928 58.601 59.208 ;
     RECT  58.061 76.32 58.673 76.488 ;
     RECT  58.561 67.584 58.709 71.448 ;
     RECT  58.529 66.144 58.745 66.168 ;
     RECT  58.673 76.464 58.745 76.488 ;
     RECT  57.881 79.248 58.781 79.752 ;
     RECT  57.089 82.272 58.813 82.728 ;
     RECT  58.709 67.584 58.925 70.872 ;
     RECT  58.349 74.592 58.925 74.952 ;
     RECT  58.925 74.928 58.961 74.952 ;
     RECT  58.925 67.584 58.993 70.776 ;
     RECT  58.277 62.976 58.997 64.2 ;
     RECT  58.457 72.864 59.033 72.888 ;
     RECT  58.813 82.272 59.033 83.064 ;
     RECT  58.597 61.056 59.065 61.944 ;
     RECT  58.993 67.248 59.069 70.776 ;
     RECT  59.033 82.56 59.105 83.064 ;
     RECT  58.601 56.928 59.141 57.384 ;
     RECT  59.069 67.248 59.171 69.864 ;
     RECT  58.133 77.904 59.173 77.928 ;
     RECT  59.065 60.336 59.177 61.944 ;
     RECT  59.173 77.904 59.269 78.072 ;
     RECT  57.868 80.88 59.269 80.904 ;
     RECT  59.177 61.056 59.321 61.944 ;
     RECT  59.269 80.88 59.429 81.528 ;
     RECT  59.141 57.072 59.465 57.384 ;
     RECT  59.321 61.536 59.573 61.944 ;
     RECT  58.997 62.976 59.677 63.096 ;
     RECT  58.781 79.728 59.749 79.752 ;
     RECT  59.429 80.88 59.749 81 ;
     RECT  59.749 79.728 59.797 81 ;
     RECT  59.269 77.28 59.804 78.072 ;
     RECT  59.804 76.896 59.821 78.072 ;
     RECT  59.797 79.2 59.869 81 ;
     RECT  58.601 58.656 59.897 59.208 ;
     RECT  59.869 79.2 59.897 79.224 ;
     RECT  59.465 57.168 59.965 57.384 ;
     RECT  59.677 62.64 60.037 63.096 ;
     RECT  58.997 64.08 60.037 64.2 ;
     RECT  59.821 76.56 60.037 78.072 ;
     RECT  59.105 82.56 60.041 82.728 ;
     RECT  59.929 71.76 60.185 71.784 ;
     RECT  59.171 67.248 60.277 69.816 ;
     RECT  60.277 67.248 60.323 70.392 ;
     RECT  60.323 70.368 60.364 70.392 ;
     RECT  58.957 65.808 60.371 65.832 ;
     RECT  60.323 67.248 60.437 69.144 ;
     RECT  59.893 73.776 60.613 73.8 ;
     RECT  59.965 57.168 60.685 57.672 ;
     RECT  60.037 75.696 60.689 78.072 ;
     RECT  59.897 59.184 60.865 59.208 ;
     RECT  60.277 71.808 60.973 71.832 ;
     RECT  60.685 57.168 60.997 57.816 ;
     RECT  60.437 67.248 61.117 68.664 ;
     RECT  60.689 76.56 61.117 78.072 ;
     RECT  59.869 80.976 61.153 81 ;
     RECT  60.613 73.776 61.297 74.088 ;
     RECT  61.117 66.768 61.369 68.664 ;
     RECT  61.117 76.56 61.436 78.648 ;
     RECT  60.865 59.184 61.477 59.88 ;
     RECT  59.573 61.536 61.532 61.56 ;
     RECT  60.037 62.64 61.532 64.2 ;
     RECT  61.369 65.952 61.621 68.664 ;
     RECT  61.621 65.424 61.669 68.664 ;
     RECT  60.973 71.808 61.693 72.696 ;
     RECT  61.297 73.776 61.693 74.952 ;
     RECT  56.704 51.888 61.808 51.912 ;
     RECT  56.704 52.992 61.808 53.016 ;
     RECT  56.704 55.152 61.808 55.176 ;
     RECT  60.997 57.024 61.808 57.816 ;
     RECT  61.477 59.184 61.808 60.408 ;
     RECT  61.532 61.536 61.808 64.2 ;
     RECT  61.669 65.232 61.808 68.664 ;
     RECT  61.693 71.808 61.808 74.952 ;
     RECT  61.436 76.56 61.808 79.464 ;
     RECT  61.153 80.976 61.808 81.144 ;
     RECT  60.041 82.704 61.808 82.728 ;
     RECT  61.808 2.148 61.912 84.252 ;
     RECT  61.912 2.418 62.104 83.982 ;
     RECT  62.104 57.024 62.165 57.432 ;
     RECT  62.104 58.656 62.165 59.88 ;
     RECT  62.104 64.56 62.165 66.648 ;
     RECT  62.104 75.936 62.237 77.592 ;
     RECT  62.104 83.712 62.243 83.736 ;
     RECT  62.237 75.984 62.633 77.592 ;
     RECT  62.104 82.656 62.741 82.68 ;
     RECT  62.165 64.56 62.777 65.448 ;
     RECT  62.104 62.688 63.029 63.288 ;
     RECT  62.104 80.448 63.029 81.144 ;
     RECT  62.104 67.68 63.097 68.52 ;
     RECT  62.104 69.6 63.097 71.016 ;
     RECT  62.104 72.336 63.097 74.952 ;
     RECT  62.633 76.752 63.097 77.592 ;
     RECT  62.104 78.624 63.097 78.648 ;
     RECT  62.104 51.888 63.109 51.912 ;
     RECT  63.097 67.68 63.137 74.952 ;
     RECT  62.165 57.024 63.165 57.384 ;
     RECT  62.165 58.656 63.173 59.208 ;
     RECT  63.165 57.12 63.209 57.384 ;
     RECT  62.777 64.56 63.317 65.256 ;
     RECT  63.029 62.688 63.385 63.096 ;
     RECT  63.029 80.448 63.452 80.472 ;
     RECT  63.137 71.04 63.493 74.952 ;
     RECT  63.452 80.208 63.539 80.472 ;
     RECT  63.493 71.04 63.58 75.384 ;
     RECT  63.097 76.752 63.673 78.648 ;
     RECT  62.104 60.96 63.677 60.984 ;
     RECT  63.317 65.232 63.677 65.256 ;
     RECT  63.58 71.04 63.677 75.048 ;
     RECT  63.673 76.464 63.677 78.648 ;
     RECT  63.5 82.032 63.683 82.056 ;
     RECT  63.677 72.336 63.785 75.048 ;
     RECT  63.385 62.16 63.893 63.096 ;
     RECT  63.785 72.816 63.929 75.048 ;
     RECT  62.165 66.624 63.961 66.648 ;
     RECT  63.137 67.68 64.001 69.624 ;
     RECT  63.173 58.8 64.037 59.208 ;
     RECT  64.001 67.68 64.037 69.528 ;
     RECT  64.037 58.8 64.073 58.824 ;
     RECT  63.929 73.344 64.073 75.048 ;
     RECT  64.073 73.344 64.145 74.952 ;
     RECT  63.893 62.16 64.172 62.184 ;
     RECT  64.145 73.536 64.181 74.952 ;
     RECT  64.172 61.44 64.259 62.184 ;
     RECT  64.037 67.68 64.259 68.376 ;
     RECT  63.539 80.448 64.361 80.472 ;
     RECT  63.677 71.04 64.549 71.064 ;
     RECT  64.037 69.504 64.595 69.528 ;
     RECT  64.549 70.656 64.636 71.064 ;
     RECT  63.277 83.808 64.757 83.832 ;
     RECT  64.259 62.16 64.865 62.184 ;
     RECT  63.961 66 64.885 66.648 ;
     RECT  64.885 66 64.931 66.744 ;
     RECT  64.259 67.824 64.931 68.376 ;
     RECT  64.933 65.52 64.969 65.544 ;
     RECT  64.931 66.72 64.972 66.744 ;
     RECT  63.677 76.464 65.077 78.264 ;
     RECT  64.181 73.536 65.125 74.424 ;
     RECT  64.969 65.424 65.149 65.544 ;
     RECT  65.125 72.816 65.171 74.424 ;
     RECT  64.636 71.04 65.185 71.064 ;
     RECT  65.077 76.464 65.189 79.224 ;
     RECT  64.931 68.352 65.437 68.376 ;
     RECT  65.171 74.352 65.509 74.424 ;
     RECT  65.171 72.816 65.581 72.84 ;
     RECT  65.509 74.352 65.581 74.616 ;
     RECT  65.185 71.04 65.585 71.448 ;
     RECT  65.437 68.352 65.689 68.616 ;
     RECT  65.581 72.432 65.729 72.84 ;
     RECT  65.149 64.416 65.989 65.544 ;
     RECT  65.989 64.416 66.035 65.688 ;
     RECT  66.035 65.664 66.076 65.688 ;
     RECT  65.989 67.296 66.089 67.32 ;
     RECT  64.933 81.504 66.133 81.528 ;
     RECT  66.133 80.64 66.179 81.528 ;
     RECT  65.189 76.464 66.188 77.448 ;
     RECT  66.179 80.64 66.22 80.664 ;
     RECT  65.189 79.2 66.24 79.224 ;
     RECT  65.585 71.04 66.293 71.064 ;
     RECT  66.293 70.656 66.332 71.064 ;
     RECT  65.689 68.352 66.373 68.904 ;
     RECT  66.188 76.464 66.481 78.12 ;
     RECT  66.332 70.128 66.553 71.064 ;
     RECT  65.581 74.352 66.877 74.712 ;
     RECT  66.373 67.584 67.045 68.904 ;
     RECT  66.553 70.128 67.045 71.64 ;
     RECT  67.045 67.584 67.093 71.64 ;
     RECT  65.729 72.816 67.093 72.84 ;
     RECT  63.109 51.648 67.208 51.912 ;
     RECT  62.104 52.992 67.208 53.016 ;
     RECT  62.104 55.152 67.208 55.176 ;
     RECT  63.209 57.168 67.208 57.384 ;
     RECT  66.035 64.416 67.208 64.44 ;
     RECT  67.093 67.584 67.208 73.224 ;
     RECT  66.877 74.304 67.208 74.712 ;
     RECT  66.481 75.696 67.208 78.12 ;
     RECT  64.501 82.704 67.208 82.728 ;
     RECT  67.208 2.148 67.312 84.252 ;
     RECT  67.312 2.418 67.504 83.982 ;
     RECT  67.504 75.648 67.565 75.816 ;
     RECT  67.504 66.336 67.619 67.272 ;
     RECT  67.504 82.704 67.619 82.728 ;
     RECT  67.619 67.248 67.645 67.272 ;
     RECT  67.504 69.552 67.853 70.68 ;
     RECT  67.504 72.24 67.889 74.664 ;
     RECT  67.504 64.416 67.925 65.208 ;
     RECT  67.925 65.184 68.033 65.208 ;
     RECT  67.889 73.488 68.147 74.664 ;
     RECT  67.504 68.352 68.213 68.376 ;
     RECT  68.147 73.488 68.321 74.424 ;
     RECT  67.565 75.648 68.321 75.672 ;
     RECT  68.321 74.4 68.429 74.424 ;
     RECT  67.889 72.24 68.465 72.264 ;
     RECT  67.853 69.552 68.573 69.768 ;
     RECT  68.573 69.552 68.681 69.576 ;
     RECT  67.504 51.648 72.608 51.912 ;
     RECT  67.504 52.992 72.608 53.016 ;
     RECT  67.504 55.152 72.608 55.176 ;
     RECT  67.504 57.168 72.608 57.384 ;
     RECT  72.608 2.148 72.712 84.252 ;
     RECT  72.712 2.418 72.904 83.982 ;
     RECT  72.904 51.648 78.008 51.912 ;
     RECT  72.904 52.992 78.008 53.016 ;
     RECT  72.904 55.152 78.008 55.176 ;
     RECT  72.904 57.168 78.008 57.384 ;
     RECT  78.008 2.148 78.112 84.252 ;
     RECT  78.112 2.418 78.304 83.982 ;
     RECT  78.304 51.648 81.101 51.912 ;
     RECT  81.101 51.888 81.317 51.912 ;
     RECT  78.304 52.992 81.857 53.016 ;
     RECT  78.304 55.152 82.073 55.176 ;
     RECT  78.304 57.168 82.145 57.384 ;
     RECT  82.145 57.168 83.408 57.192 ;
     RECT  83.408 2.148 83.512 84.252 ;
     RECT  83.512 2.418 83.704 83.982 ;
     RECT  83.704 49.488 83.801 49.512 ;
     RECT  83.704 32.688 84.841 33.192 ;
     RECT  84.841 32.688 84.877 33.48 ;
     RECT  83.704 52.08 85.417 54.12 ;
     RECT  84.877 32.688 85.453 34.344 ;
     RECT  85.417 52.08 85.489 54.312 ;
     RECT  85.453 32.688 86.209 34.44 ;
     RECT  86.209 32.688 86.245 34.536 ;
     RECT  85.489 51.504 86.245 54.312 ;
     RECT  86.245 51.504 86.281 54.504 ;
     RECT  86.245 32.496 86.364 34.728 ;
     RECT  86.281 51.408 86.364 54.504 ;
     RECT  86.364 32.496 86.393 32.52 ;
     RECT  86.364 34.704 86.393 34.728 ;
     RECT  86.364 54.48 86.393 54.504 ;
    LAYER M5 ;
     RECT  42.768 0.016 42.888 0.131 ;
     RECT  42.864 0.131 42.888 1.763 ;
     RECT  2.4 2.137 2.52 2.151 ;
     RECT  7.8 2.137 7.92 2.151 ;
     RECT  13.2 2.137 13.32 2.151 ;
     RECT  18.6 2.137 18.72 2.151 ;
     RECT  24 2.137 24.12 2.151 ;
     RECT  29.4 2.137 29.52 2.151 ;
     RECT  34.8 2.137 34.92 2.151 ;
     RECT  40.2 2.137 40.32 2.151 ;
     RECT  45.6 2.137 45.72 2.151 ;
     RECT  51 2.137 51.12 2.151 ;
     RECT  56.4 2.137 56.52 2.151 ;
     RECT  61.8 2.137 61.92 2.151 ;
     RECT  67.2 2.137 67.32 2.151 ;
     RECT  72.6 2.137 72.72 2.151 ;
     RECT  78 2.137 78.12 2.151 ;
     RECT  83.4 2.137 83.52 2.151 ;
     RECT  43.008 3.685 43.032 44.723 ;
     RECT  38.592 44.677 38.616 44.965 ;
     RECT  45.6 2.151 45.912 51.877 ;
     RECT  45.6 51.877 46.056 52.981 ;
     RECT  45.6 52.981 46.104 55.141 ;
     RECT  34.8 2.151 35.112 55.909 ;
     RECT  38.16 44.965 38.616 55.955 ;
     RECT  29.4 2.151 29.712 56.485 ;
     RECT  40.2 2.151 40.512 56.485 ;
     RECT  56.4 2.151 56.712 57.013 ;
     RECT  61.8 2.151 62.112 57.013 ;
     RECT  63.12 51.637 63.144 57.013 ;
     RECT  34.8 55.909 35.688 57.059 ;
     RECT  47.568 55.237 47.592 57.059 ;
     RECT  61.008 57.013 63.144 57.059 ;
     RECT  56.304 57.013 56.712 57.061 ;
     RECT  56.304 57.061 57 57.251 ;
     RECT  56.4 57.251 57 57.347 ;
     RECT  51 2.151 51.312 57.541 ;
     RECT  44.448 56.053 44.472 57.587 ;
     RECT  28.56 56.485 29.712 57.635 ;
     RECT  61.008 57.059 62.232 57.827 ;
     RECT  50.64 57.541 51.312 57.875 ;
     RECT  47.904 57.685 47.928 57.973 ;
     RECT  24 2.151 24.312 58.117 ;
     RECT  34.8 57.059 35.112 58.117 ;
     RECT  26.784 56.101 26.808 58.163 ;
     RECT  40.2 56.485 40.728 58.547 ;
     RECT  43.872 58.117 43.896 58.645 ;
     RECT  61.8 57.827 62.232 58.691 ;
     RECT  24 58.117 25.08 58.787 ;
     RECT  43.872 58.645 44.328 58.787 ;
     RECT  56.4 57.347 56.712 59.077 ;
     RECT  56.4 59.077 56.808 59.173 ;
     RECT  61.8 58.691 62.112 59.173 ;
     RECT  56.016 59.173 56.808 59.219 ;
     RECT  38.16 55.955 38.184 59.221 ;
     RECT  53.28 58.981 53.304 59.221 ;
     RECT  34.512 58.117 35.112 59.267 ;
     RECT  56.016 59.219 56.712 59.315 ;
     RECT  34.8 59.267 35.112 59.509 ;
     RECT  38.16 59.221 38.472 59.555 ;
     RECT  53.28 59.221 54.168 59.843 ;
     RECT  47.904 57.973 48.072 59.845 ;
     RECT  49.584 57.829 49.608 59.891 ;
     RECT  43.872 58.787 43.896 59.987 ;
     RECT  38.448 59.555 38.472 60.275 ;
     RECT  53.28 59.843 53.304 60.373 ;
     RECT  42.048 59.029 42.072 60.419 ;
     RECT  27.456 58.645 27.48 60.851 ;
     RECT  34.8 59.509 35.4 60.949 ;
     RECT  47.472 59.845 48.072 60.949 ;
     RECT  47.472 60.949 49.032 61.045 ;
     RECT  47.472 61.045 49.128 61.091 ;
     RECT  51 57.875 51.312 61.093 ;
     RECT  36.624 59.749 36.648 61.189 ;
     RECT  30.816 60.421 30.84 61.331 ;
     RECT  56.4 59.315 56.712 61.381 ;
     RECT  36.624 61.189 37.128 61.669 ;
     RECT  32.496 59.845 32.52 61.861 ;
     RECT  44.448 61.573 44.472 62.101 ;
     RECT  50.112 61.093 51.312 62.149 ;
     RECT  52.464 60.373 53.304 62.149 ;
     RECT  32.496 61.861 32.856 62.195 ;
     RECT  49.104 61.091 49.128 62.195 ;
     RECT  50.112 62.149 53.304 62.195 ;
     RECT  60.96 59.173 62.112 62.675 ;
     RECT  32.832 62.195 32.856 62.677 ;
     RECT  34.464 60.949 35.4 62.677 ;
     RECT  32.832 62.677 35.4 62.723 ;
     RECT  61.584 62.675 62.112 62.723 ;
     RECT  47.472 61.091 48.072 62.771 ;
     RECT  53.28 62.195 53.304 62.965 ;
     RECT  55.824 61.381 56.712 63.013 ;
     RECT  50.112 62.195 52.296 63.059 ;
     RECT  0.192 25.381 0.216 63.107 ;
     RECT  38.784 62.869 38.808 63.251 ;
     RECT  36.432 61.669 37.128 63.347 ;
     RECT  51 63.059 52.296 63.491 ;
     RECT  33.792 62.723 35.4 63.779 ;
     RECT  43.584 62.101 44.472 63.779 ;
     RECT  53.28 62.965 54.072 63.779 ;
     RECT  28.8 57.635 29.712 63.781 ;
     RECT  55.68 63.013 56.712 63.875 ;
     RECT  51 63.491 52.248 64.357 ;
     RECT  54 63.779 54.072 64.357 ;
     RECT  67.2 2.151 67.512 64.405 ;
     RECT  33.792 63.779 35.112 64.451 ;
     RECT  24 58.787 24.312 64.885 ;
     RECT  49.68 64.357 49.704 64.933 ;
     RECT  50.832 64.357 52.248 64.933 ;
     RECT  25.632 64.165 25.656 65.027 ;
     RECT  49.68 64.933 52.248 65.027 ;
     RECT  55.296 64.933 55.32 65.125 ;
     RECT  56.4 63.875 56.712 65.125 ;
     RECT  55.296 65.125 56.712 65.171 ;
     RECT  61.68 62.723 62.112 65.267 ;
     RECT  28.8 63.781 30.264 65.413 ;
     RECT  28.56 65.413 30.264 65.509 ;
     RECT  34.464 64.451 35.112 65.509 ;
     RECT  36.432 63.347 36.456 65.509 ;
     RECT  28.512 65.509 30.264 65.603 ;
     RECT  34.464 65.509 36.456 65.845 ;
     RECT  64.224 61.429 64.248 66.085 ;
     RECT  55.728 65.171 56.712 66.133 ;
     RECT  41.568 64.357 41.592 66.179 ;
     RECT  49.68 65.027 51.312 66.179 ;
     RECT  54 64.357 54.12 66.179 ;
     RECT  43.584 63.779 43.608 66.323 ;
     RECT  58.128 64.405 58.152 66.467 ;
     RECT  28.512 65.603 29.712 66.515 ;
     RECT  23.136 64.885 24.312 66.707 ;
     RECT  33.6 65.845 36.456 66.755 ;
     RECT  45.6 55.141 46.152 67.237 ;
     RECT  28.56 66.515 29.712 67.283 ;
     RECT  60.336 65.797 60.36 67.283 ;
     RECT  67.2 64.405 67.608 67.283 ;
     RECT  50.064 66.179 51.312 67.523 ;
     RECT  66 64.933 66.024 67.573 ;
     RECT  67.2 67.283 67.512 67.573 ;
     RECT  61.8 65.267 62.112 67.669 ;
     RECT  45.6 67.237 46.392 67.717 ;
     RECT  31.296 66.229 31.32 67.765 ;
     RECT  36.432 66.755 36.456 67.765 ;
     RECT  28.8 67.283 29.712 67.811 ;
     RECT  30.96 67.765 31.32 67.811 ;
     RECT  36.144 67.765 36.456 67.811 ;
     RECT  50.88 67.523 51.312 67.813 ;
     RECT  52.704 67.285 52.728 67.813 ;
     RECT  64.224 66.085 64.92 67.859 ;
     RECT  26.064 65.989 26.088 68.003 ;
     RECT  45.168 67.717 46.392 68.195 ;
     RECT  50.88 67.813 52.728 68.339 ;
     RECT  24 66.707 24.312 68.341 ;
     RECT  33.6 66.755 35.112 68.341 ;
     RECT  36.144 67.811 36.168 68.341 ;
     RECT  66 67.573 67.512 68.341 ;
     RECT  64.224 67.859 64.248 68.387 ;
     RECT  61.008 67.669 62.112 68.675 ;
     RECT  66 68.341 67.608 68.915 ;
     RECT  55.68 66.133 56.712 69.011 ;
     RECT  33.6 68.341 36.168 69.059 ;
     RECT  50.88 68.339 51.816 69.155 ;
     RECT  24 68.341 25.08 69.493 ;
     RECT  30.96 67.811 30.984 69.493 ;
     RECT  54.096 66.179 54.12 69.541 ;
     RECT  49.536 68.821 49.56 69.587 ;
     RECT  23.28 69.493 25.08 69.683 ;
     RECT  54.096 69.541 54.696 69.827 ;
     RECT  59.136 68.917 59.16 69.875 ;
     RECT  29.4 67.811 29.712 70.069 ;
     RECT  30.96 69.493 31.848 70.069 ;
     RECT  61.8 68.675 62.112 70.069 ;
     RECT  29.4 70.069 31.848 70.259 ;
     RECT  66.384 68.915 67.608 70.645 ;
     RECT  64.56 69.493 64.584 70.691 ;
     RECT  34.464 69.059 36.168 70.739 ;
     RECT  41.52 70.069 41.544 70.739 ;
     RECT  34.464 70.739 35.304 70.931 ;
     RECT  61.8 70.069 62.232 70.981 ;
     RECT  61.8 70.981 62.424 71.029 ;
     RECT  66.336 70.645 67.608 71.075 ;
     RECT  23.28 69.683 24.312 71.077 ;
     RECT  20.352 70.069 20.376 71.123 ;
     RECT  56.4 69.011 56.712 71.173 ;
     RECT  40.2 58.547 40.512 71.221 ;
     RECT  45.6 68.195 46.152 71.269 ;
     RECT  29.4 70.259 30.648 71.317 ;
     RECT  34.464 70.931 35.208 71.509 ;
     RECT  50.88 69.155 51.312 71.509 ;
     RECT  23.28 71.077 24.504 71.651 ;
     RECT  29.4 71.317 30.744 71.651 ;
     RECT  18.6 2.151 18.912 71.797 ;
     RECT  28.272 71.605 28.296 71.797 ;
     RECT  29.4 71.651 30.648 71.797 ;
     RECT  28.272 71.797 30.648 71.843 ;
     RECT  60.288 69.493 60.312 71.843 ;
     RECT  50.88 71.509 52.152 71.891 ;
     RECT  39.696 71.221 40.512 71.939 ;
     RECT  49.536 70.645 49.56 72.131 ;
     RECT  56.4 71.173 57.048 72.131 ;
     RECT  67.2 71.075 67.608 72.229 ;
     RECT  54.096 69.827 54.12 72.277 ;
     RECT  45.36 71.269 46.152 72.371 ;
     RECT  61.8 71.029 63.192 72.371 ;
     RECT  33.6 71.509 35.208 72.373 ;
     RECT  33.6 72.373 35.304 72.419 ;
     RECT  53.52 72.277 54.12 72.419 ;
     RECT  34.8 72.419 35.304 72.611 ;
     RECT  28.272 71.843 29.832 72.659 ;
     RECT  24 71.651 24.504 72.851 ;
     RECT  33.6 72.419 33.624 72.901 ;
     RECT  53.52 72.419 53.544 72.995 ;
     RECT  56.4 72.131 56.808 72.995 ;
     RECT  45.6 72.371 46.152 72.997 ;
     RECT  33.024 72.901 33.624 73.043 ;
     RECT  67.104 72.229 67.608 73.235 ;
     RECT  45.6 72.997 46.584 73.283 ;
     RECT  29.4 72.659 29.832 73.379 ;
     RECT  36.864 72.325 36.888 73.477 ;
     RECT  67.2 73.235 67.608 73.477 ;
     RECT  36.864 73.477 37.848 73.523 ;
     RECT  61.8 72.371 62.112 73.525 ;
     RECT  63.168 72.371 63.192 73.525 ;
     RECT  33.024 73.043 33.048 73.571 ;
     RECT  65.136 72.805 65.16 73.571 ;
     RECT  34.8 72.611 35.208 73.909 ;
     RECT  61.8 73.525 63.192 74.053 ;
     RECT  57.936 72.805 57.96 74.099 ;
     RECT  37.824 73.523 37.848 74.339 ;
     RECT  18.6 71.797 19.608 74.485 ;
     RECT  28.272 72.659 28.296 74.581 ;
     RECT  29.4 73.379 29.712 74.581 ;
     RECT  34.32 73.909 35.208 74.581 ;
     RECT  45.6 73.283 46.152 74.581 ;
     RECT  40.2 71.939 40.512 74.629 ;
     RECT  45.504 74.581 46.344 74.629 ;
     RECT  22.848 72.901 22.872 74.723 ;
     RECT  28.272 74.581 29.712 74.723 ;
     RECT  34.32 74.581 35.352 74.965 ;
     RECT  17.904 74.485 19.608 75.203 ;
     RECT  56.4 72.995 56.712 75.205 ;
     RECT  21.6 74.485 21.624 75.251 ;
     RECT  25.824 74.053 25.848 75.299 ;
     RECT  61.8 74.053 63.528 75.395 ;
     RECT  42.768 74.533 42.792 75.635 ;
     RECT  67.2 73.477 68.136 75.683 ;
     RECT  45.504 74.629 46.536 75.685 ;
     RECT  47.904 62.771 48.072 75.685 ;
     RECT  67.2 75.683 67.608 75.685 ;
     RECT  44.976 75.685 46.536 75.733 ;
     RECT  31.824 70.259 31.848 75.781 ;
     RECT  37.632 74.821 37.656 75.827 ;
     RECT  54.336 74.053 54.36 75.827 ;
     RECT  39.984 74.629 40.512 75.923 ;
     RECT  30.816 75.109 30.84 75.971 ;
     RECT  34.224 74.965 35.352 76.357 ;
     RECT  56.4 75.205 56.856 76.499 ;
     RECT  24 72.851 24.312 76.597 ;
     RECT  33.696 76.357 35.352 76.739 ;
     RECT  61.8 75.395 62.808 76.741 ;
     RECT  33.696 76.739 35.112 76.931 ;
     RECT  61.8 76.741 63.288 76.979 ;
     RECT  66.72 75.685 67.608 76.981 ;
     RECT  18.6 75.203 19.608 77.221 ;
     RECT  59.856 76.885 59.88 77.269 ;
     RECT  24 76.597 24.504 77.459 ;
     RECT  61.8 76.979 62.808 77.459 ;
     RECT  59.28 77.269 59.88 77.555 ;
     RECT  43.584 76.357 43.608 77.557 ;
     RECT  44.592 75.733 46.536 77.557 ;
     RECT  37.296 76.069 37.32 77.747 ;
     RECT  31.824 75.781 31.896 77.843 ;
     RECT  56.4 76.499 56.712 77.941 ;
     RECT  31.824 77.843 31.848 78.037 ;
     RECT  43.584 77.557 46.536 78.131 ;
     RECT  66.24 76.981 67.608 78.131 ;
     RECT  31.392 78.037 31.848 78.181 ;
     RECT  51 71.891 52.152 78.469 ;
     RECT  38.736 78.037 38.76 78.565 ;
     RECT  31.344 78.181 31.848 78.613 ;
     RECT  38.352 78.565 38.76 78.613 ;
     RECT  61.8 77.459 62.112 78.613 ;
     RECT  54.24 77.557 54.264 78.659 ;
     RECT  55.728 77.941 56.712 78.659 ;
     RECT  18.6 77.221 20.568 78.707 ;
     RECT  61.488 78.613 62.112 79.475 ;
     RECT  31.008 78.613 31.848 79.573 ;
     RECT  51 78.469 52.392 79.573 ;
     RECT  31.008 79.573 32.328 79.717 ;
     RECT  31.008 79.717 32.856 79.765 ;
     RECT  33.84 76.931 35.112 79.765 ;
     RECT  38.352 78.613 39.048 79.765 ;
     RECT  40.2 75.923 40.512 79.765 ;
     RECT  50.496 79.573 52.392 79.765 ;
     RECT  50.496 79.765 52.632 80.005 ;
     RECT  24 77.459 24.312 80.101 ;
     RECT  41.616 79.573 41.64 80.387 ;
     RECT  28.272 74.723 28.296 80.389 ;
     RECT  29.4 74.723 29.712 80.389 ;
     RECT  31.008 79.765 35.112 80.389 ;
     RECT  63.504 78.613 63.528 80.437 ;
     RECT  30.816 80.389 35.736 80.483 ;
     RECT  38.352 79.765 40.512 80.483 ;
     RECT  63.504 80.437 63.672 80.483 ;
     RECT  38.352 80.483 38.952 80.675 ;
     RECT  25.632 79.765 25.656 80.819 ;
     RECT  47.904 75.685 48.552 80.821 ;
     RECT  57.792 79.189 57.816 80.915 ;
     RECT  50.496 80.005 53.016 80.917 ;
     RECT  28.272 80.389 29.712 80.963 ;
     RECT  59.28 77.555 59.832 81.011 ;
     RECT  30.816 80.483 32.856 81.059 ;
     RECT  38.592 80.675 38.952 81.059 ;
     RECT  47.904 80.821 49.032 81.059 ;
     RECT  28.752 80.963 29.712 81.347 ;
     RECT  31.344 81.059 32.856 81.445 ;
     RECT  34.08 80.483 35.736 81.445 ;
     RECT  18.6 78.707 19.608 81.539 ;
     RECT  38.928 81.059 38.952 81.539 ;
     RECT  59.28 81.011 59.304 81.539 ;
     RECT  66.144 79.189 66.168 81.539 ;
     RECT  26.784 77.701 26.808 82.021 ;
     RECT  47.904 81.059 48.552 82.021 ;
     RECT  63.648 80.483 63.672 82.021 ;
     RECT  26.688 82.021 26.808 82.067 ;
     RECT  63.552 82.021 63.672 82.067 ;
     RECT  50.4 80.917 53.016 82.115 ;
     RECT  55.92 78.659 56.712 82.115 ;
     RECT  50.448 82.115 53.016 82.453 ;
     RECT  54.192 81.637 54.216 82.453 ;
     RECT  31.344 81.445 35.736 82.501 ;
     RECT  61.8 79.475 62.112 82.645 ;
     RECT  23.664 80.101 24.312 82.691 ;
     RECT  31.296 82.501 35.736 82.691 ;
     RECT  50.448 82.453 54.216 82.691 ;
     RECT  67.2 78.131 67.608 82.739 ;
     RECT  26.688 82.067 26.712 83.171 ;
     RECT  31.296 82.691 35.112 83.219 ;
     RECT  21.648 82.117 21.672 83.267 ;
     RECT  52.416 82.691 54.216 83.267 ;
     RECT  52.416 83.267 53.016 83.363 ;
     RECT  47.904 82.021 49.32 83.701 ;
     RECT  50.448 82.691 51.312 83.701 ;
     RECT  61.8 82.645 62.232 83.747 ;
     RECT  52.656 83.363 53.016 83.843 ;
     RECT  63.552 82.067 63.576 83.843 ;
     RECT  54.192 83.267 54.216 83.891 ;
     RECT  52.656 83.843 52.968 83.987 ;
     RECT  44.352 78.131 46.536 84.181 ;
     RECT  2.4 2.151 2.712 84.249 ;
     RECT  7.8 2.151 8.112 84.249 ;
     RECT  13.2 2.151 13.512 84.249 ;
     RECT  18.6 81.539 18.912 84.249 ;
     RECT  24 82.691 24.312 84.249 ;
     RECT  29.4 81.347 29.712 84.249 ;
     RECT  31.344 83.219 35.112 84.249 ;
     RECT  40.2 80.483 40.512 84.249 ;
     RECT  47.904 83.701 51.312 84.249 ;
     RECT  56.4 82.115 56.712 84.249 ;
     RECT  61.8 83.747 62.112 84.249 ;
     RECT  67.2 82.739 67.512 84.249 ;
     RECT  72.6 2.151 72.912 84.249 ;
     RECT  78 2.151 78.312 84.249 ;
     RECT  83.4 2.151 83.712 84.249 ;
     RECT  2.4 84.249 2.52 84.263 ;
     RECT  7.8 84.249 7.92 84.263 ;
     RECT  13.2 84.249 13.32 84.263 ;
     RECT  18.6 84.249 18.72 84.263 ;
     RECT  24 84.249 24.12 84.263 ;
     RECT  29.4 84.249 29.52 84.263 ;
     RECT  31.344 84.249 34.92 84.263 ;
     RECT  40.2 84.249 40.32 84.263 ;
     RECT  47.904 84.249 51.12 84.263 ;
     RECT  56.4 84.249 56.52 84.263 ;
     RECT  61.8 84.249 61.92 84.263 ;
     RECT  67.2 84.249 67.32 84.263 ;
     RECT  72.6 84.249 72.72 84.263 ;
     RECT  78 84.249 78.12 84.263 ;
     RECT  83.4 84.249 83.52 84.263 ;
     RECT  52.656 83.987 52.68 84.371 ;
     RECT  31.344 84.263 34.728 85.477 ;
     RECT  44.208 84.181 46.536 85.477 ;
     RECT  47.904 84.263 50.952 85.477 ;
     RECT  30.96 85.477 34.728 86.149 ;
     RECT  30.864 86.149 34.728 86.197 ;
     RECT  44.208 85.477 50.952 86.197 ;
     RECT  30.864 86.197 34.824 86.245 ;
     RECT  30.768 86.245 34.92 86.352 ;
     RECT  44.208 86.197 51.048 86.352 ;
     RECT  62.112 51.637 63.12 57.013 ;
     RECT  46.152 55.237 47.568 57.059 ;
     RECT  44.472 56.053 45.6 57.587 ;
     RECT  44.448 57.587 45.6 58.117 ;
     RECT  28.56 57.635 28.8 58.645 ;
     RECT  61.008 57.827 61.8 59.173 ;
     RECT  49.608 57.829 50.64 57.875 ;
     RECT  49.608 57.875 51 59.891 ;
     RECT  48.072 57.973 49.584 59.891 ;
     RECT  43.896 58.117 45.6 58.645 ;
     RECT  27.48 58.645 28.8 60.851 ;
     RECT  44.328 58.645 45.6 58.787 ;
     RECT  35.4 59.749 36.624 61.669 ;
     RECT  46.152 59.845 47.472 62.771 ;
     RECT  48.072 59.891 51 60.949 ;
     RECT  51.312 60.373 52.464 62.149 ;
     RECT  29.712 60.421 30.816 61.331 ;
     RECT  49.032 60.949 51 61.045 ;
     RECT  49.128 61.045 51 61.093 ;
     RECT  48.072 61.091 49.104 62.195 ;
     RECT  49.128 61.093 50.112 62.195 ;
     RECT  44.472 61.573 45.6 63.779 ;
     RECT  35.4 61.669 36.432 63.779 ;
     RECT  52.296 62.195 53.28 63.491 ;
     RECT  38.808 62.869 40.2 63.251 ;
     RECT  50.112 63.059 51 64.357 ;
     RECT  52.248 63.491 53.28 63.779 ;
     RECT  35.112 63.779 36.432 65.509 ;
     RECT  55.68 63.875 56.4 64.933 ;
     RECT  24.312 64.165 25.632 65.027 ;
     RECT  40.512 64.357 41.568 66.179 ;
     RECT  49.704 64.357 50.832 64.933 ;
     RECT  56.712 64.405 58.128 66.467 ;
     RECT  33.792 64.451 34.464 65.845 ;
     RECT  54.12 64.933 55.296 65.171 ;
     RECT  55.32 64.933 56.4 65.125 ;
     RECT  66.024 64.933 67.2 67.573 ;
     RECT  55.68 65.171 55.728 66.133 ;
     RECT  61.68 65.267 61.8 65.797 ;
     RECT  60.36 65.797 61.8 67.283 ;
     RECT  64.92 66.085 66 67.859 ;
     RECT  54 66.179 54.096 67.285 ;
     RECT  35.112 66.755 36.432 67.765 ;
     RECT  46.392 67.237 47.904 68.195 ;
     RECT  61.008 67.283 61.8 67.669 ;
     RECT  67.512 67.283 67.608 68.341 ;
     RECT  51.312 67.285 52.704 67.813 ;
     RECT  52.728 67.285 54.096 68.339 ;
     RECT  50.064 67.523 50.88 68.821 ;
     RECT  29.712 67.765 30.96 70.069 ;
     RECT  35.112 67.765 36.144 68.341 ;
     RECT  61.008 68.675 61.8 69.493 ;
     RECT  48.072 68.821 49.536 69.587 ;
     RECT  49.56 68.821 50.88 69.587 ;
     RECT  59.16 69.493 60.288 69.875 ;
     RECT  60.312 69.493 61.8 71.843 ;
     RECT  48.072 69.587 50.88 70.645 ;
     RECT  24.312 69.683 24.504 71.077 ;
     RECT  18.912 70.069 20.352 71.123 ;
     RECT  40.512 70.069 41.52 70.739 ;
     RECT  30.648 70.259 31.824 71.317 ;
     RECT  48.072 70.645 49.536 72.131 ;
     RECT  49.56 70.645 50.88 71.891 ;
     RECT  35.208 70.931 35.304 72.373 ;
     RECT  67.104 71.075 67.2 72.229 ;
     RECT  18.912 71.123 19.608 71.797 ;
     RECT  30.744 71.317 31.824 71.651 ;
     RECT  28.296 71.605 29.4 71.797 ;
     RECT  23.28 71.651 24 72.901 ;
     RECT  30.648 71.651 31.824 71.843 ;
     RECT  49.56 71.891 51 72.131 ;
     RECT  56.808 72.131 57.048 72.805 ;
     RECT  52.152 72.277 53.52 72.995 ;
     RECT  62.112 72.371 63.168 73.525 ;
     RECT  33.624 72.419 34.8 73.043 ;
     RECT  28.296 72.659 29.4 74.581 ;
     RECT  56.808 72.805 57.936 72.995 ;
     RECT  24.312 72.851 24.504 74.053 ;
     RECT  22.872 72.901 24 74.723 ;
     RECT  31.848 72.901 33.024 73.571 ;
     RECT  56.712 72.995 57.936 74.099 ;
     RECT  46.584 72.997 47.904 73.283 ;
     RECT  33.048 73.043 34.8 73.571 ;
     RECT  46.152 73.283 47.904 74.581 ;
     RECT  37.632 73.523 37.824 74.339 ;
     RECT  34.224 73.571 34.8 73.909 ;
     RECT  34.224 73.909 34.32 74.965 ;
     RECT  24.312 74.053 25.824 75.299 ;
     RECT  56.712 74.099 56.856 75.205 ;
     RECT  37.632 74.339 37.656 74.821 ;
     RECT  21.624 74.485 22.848 74.723 ;
     RECT  46.344 74.581 47.904 74.629 ;
     RECT  46.536 74.629 47.904 85.477 ;
     RECT  28.296 74.723 29.4 80.389 ;
     RECT  29.712 75.109 30.816 75.971 ;
     RECT  30.84 75.109 31.824 75.971 ;
     RECT  24.312 75.299 24.504 76.597 ;
     RECT  62.808 75.395 63.288 76.741 ;
     RECT  43.608 76.357 44.592 77.557 ;
     RECT  62.112 77.459 62.808 78.613 ;
     RECT  26.808 77.701 28.272 80.963 ;
     RECT  54.264 77.941 55.728 78.659 ;
     RECT  38.76 78.037 40.2 78.613 ;
     RECT  66.24 78.131 67.2 79.189 ;
     RECT  29.712 78.613 31.008 80.389 ;
     RECT  39.048 78.613 40.2 79.765 ;
     RECT  62.112 78.613 63.504 80.483 ;
     RECT  56.712 79.189 57.792 80.915 ;
     RECT  57.816 79.189 59.28 80.915 ;
     RECT  66.168 79.189 67.2 81.539 ;
     RECT  32.328 79.573 33.84 79.717 ;
     RECT  40.512 79.573 41.616 80.387 ;
     RECT  32.856 79.717 33.84 79.765 ;
     RECT  24.312 79.765 25.632 80.819 ;
     RECT  25.656 79.765 26.784 80.819 ;
     RECT  29.712 80.389 30.816 81.059 ;
     RECT  32.856 80.483 34.08 81.445 ;
     RECT  38.952 80.483 40.2 81.539 ;
     RECT  26.688 80.819 26.784 82.021 ;
     RECT  49.032 80.821 50.496 80.917 ;
     RECT  49.032 80.917 50.4 81.059 ;
     RECT  31.296 81.059 31.344 82.501 ;
     RECT  48.552 81.059 50.4 82.021 ;
     RECT  53.016 81.637 54.192 82.453 ;
     RECT  49.32 82.021 50.4 82.115 ;
     RECT  62.112 82.021 63.552 82.645 ;
     RECT  49.32 82.115 50.448 83.701 ;
     RECT  62.232 82.645 63.552 83.747 ;
     RECT  51.312 82.691 52.416 83.363 ;
     RECT  53.016 83.267 54.192 83.843 ;
     RECT  51.312 83.363 52.656 84.249 ;
     RECT  62.112 83.747 63.552 83.843 ;
     RECT  52.968 83.843 54.192 83.891 ;
  END
END ot_hgi_sm_pub_smrg_l1
END LIBRARY
